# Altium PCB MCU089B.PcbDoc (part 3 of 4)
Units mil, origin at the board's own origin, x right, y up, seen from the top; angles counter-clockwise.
Board outline 2300 x 5500 mil, 4 copper layers (Top Signal, GND, PWR, Bottom Signal), stack 61.6 mil thick; 261 components, 208 nets, 964 pads, 377 vias.

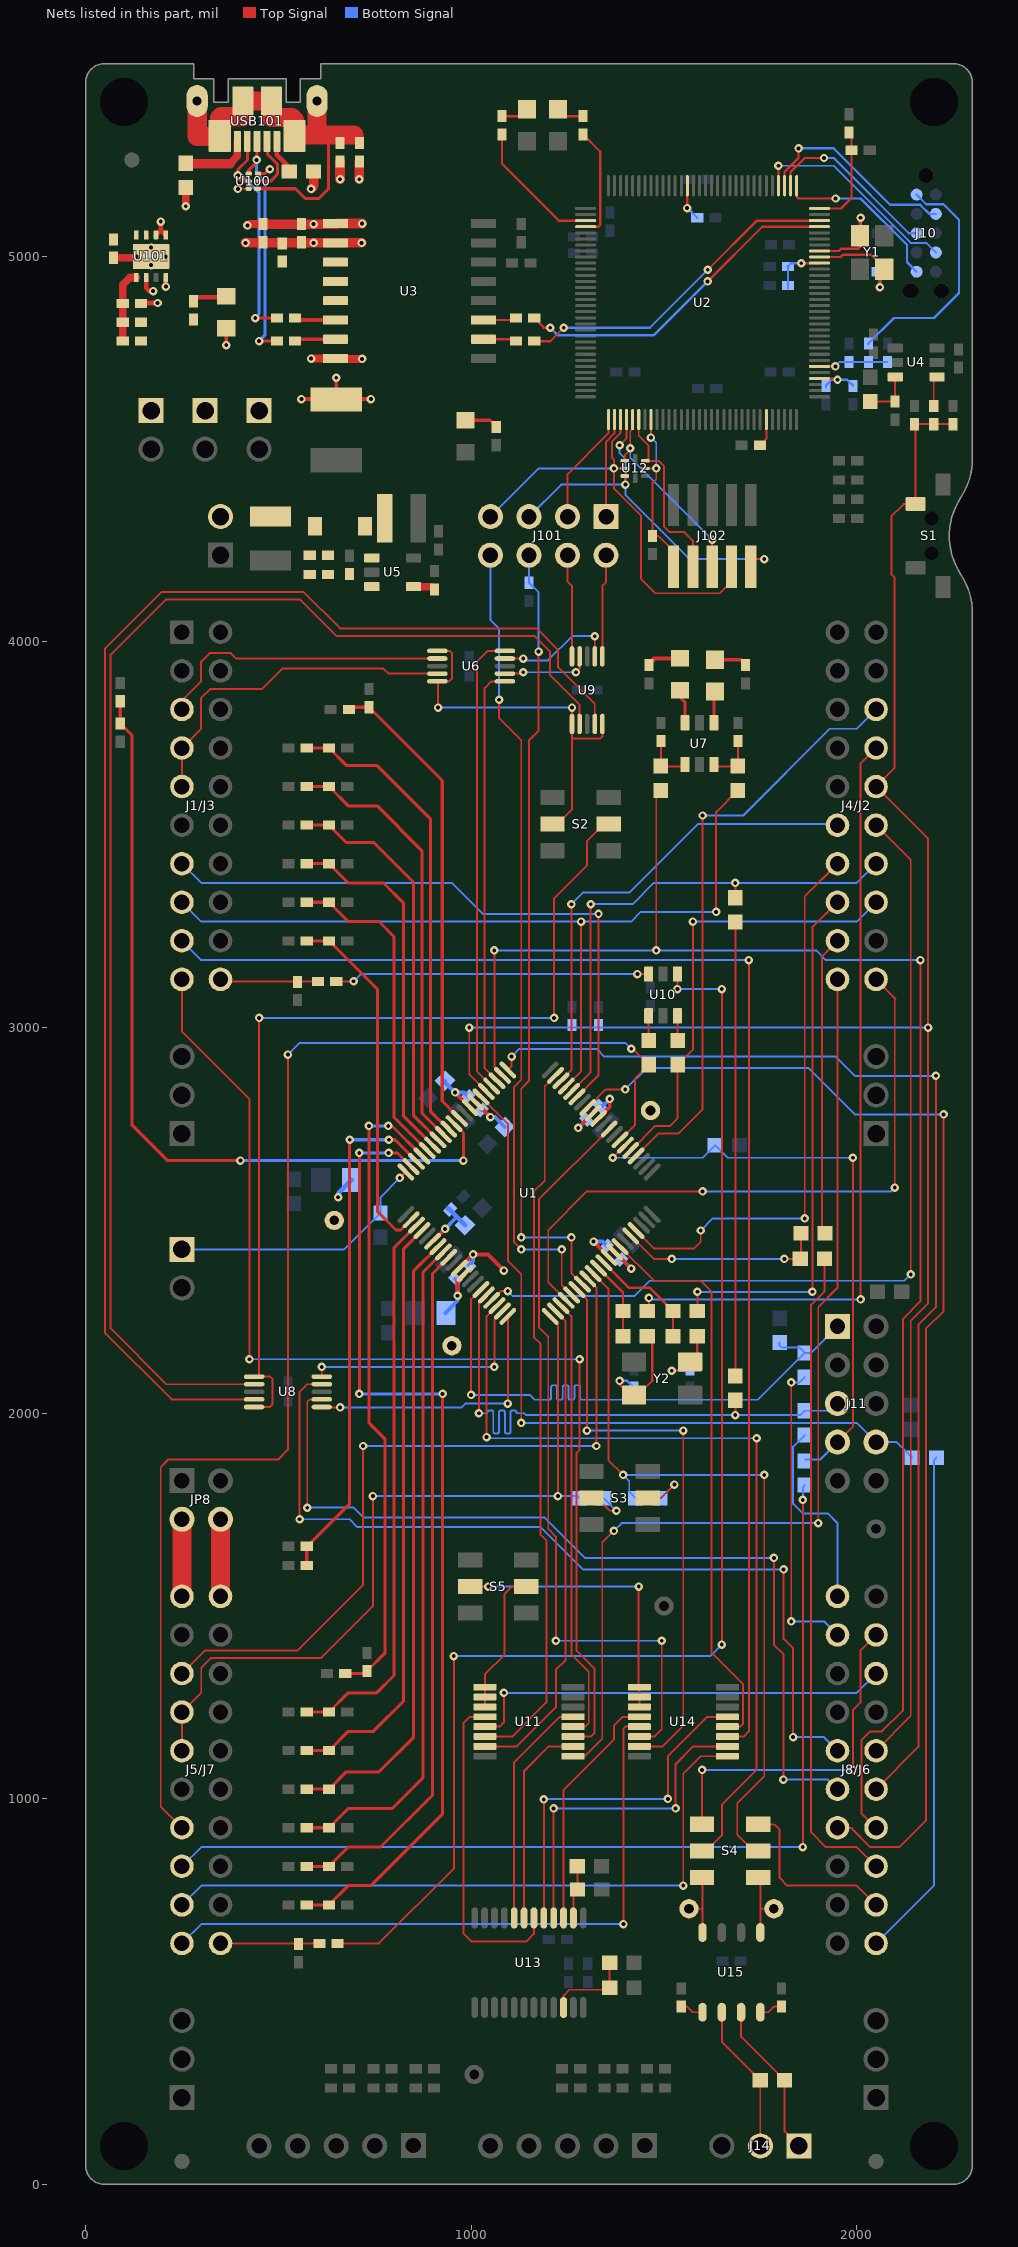
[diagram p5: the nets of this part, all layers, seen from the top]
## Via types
v1: diameter 22, hole 10, Top Signal to Bottom Signal, tented both sides, 377 vias

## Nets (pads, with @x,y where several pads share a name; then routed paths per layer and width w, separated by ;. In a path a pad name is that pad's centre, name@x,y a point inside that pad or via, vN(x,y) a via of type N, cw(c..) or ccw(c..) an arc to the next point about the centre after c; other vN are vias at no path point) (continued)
GPIO9: J1/J3.7 U1.75 | length 1631.7
  Top Signal w5: U1.75@1274.56,2820.4 1330.24,2876.08 v1(1330.24,3295)
  Bottom Signal w5: J1/J3.7@250,3425 300,3375 950,3375 1030,3295 v1(1330.24,3295)
GPIO10: J4/J2.14 R81.2 U1.76 | length 1328.1
  Top Signal w5: U1.76@1260.64,2834.32 1310,2883.68 v1(1310,3320) ; R81.2@1685,3336.5 v1(1685,3375)
  Bottom Signal w5: v1(1310,3320) 1418.62,3320 1473.62,3375 v1(1685,3375) 2000,3375 J4/J2.14@2050,3425
GPIO11: J4/J2.15 U1.37 | length 2327.6
  Top Signal w5: U1.37@1053.24,2292.86 1076.88,2316.5 v1(1095,2316.5) ; J4/J2.15@2050,3525 2140,3435 v1(2140,2360)
  Bottom Signal w5: v1(1095,2316.5) 1108.01,2303.48 1423.1,2303.48 1463.12,2343.5 2123.5,2343.5 v1(2140,2360)
GPIO12_BP: J8/J6.80 R50.2 | length 516.6
  Bottom Signal w5: R50.2@1865,1943.5 1835,1913.5 1835,1765.12 1860.12,1740 1925,1740 1950,1715 J8/J6.80@1950,1525
GPIO12_FSIRXD0: J11.5 R50.1 R51.1 U1.36 | length 1533.1
  Top Signal w5: v1(1020,2000) 1020,2287.45 U1.36@1039.32,2306.78 ; R51.1@1680,2033.5 1685,2028.5 v1(1685,1995)
  Bottom Signal w5: v1(1020,2000) 1034.84,2000 1039.34,2000 ccw(c1039.34,2003) 1042.34,2003 cw(c1046.84,2003) 1046.84,2007.5 1052.84,2007.5 cw(c1052.84,2003) 1057.34,2003 1057.34,2000 1057.34,1952 ccw(c1061.84,1952) 1061.84,1947.5 1067.84,1947.5 ccw(c1067.84,1952) 1072.34,1952 1072.34,2000 1072.34,2003 cw(c1076.84,2003) 1076.84,2007.5 1082.84,2007.5 cw(c1082.84,2003) 1087.34,2003 1087.34,2000 1087.34,1952 ccw(c1091.84,1952) 1091.84,1947.5 1097.84,1947.5 ccw(c1097.84,1952) 1102.34,1952 1102.34,2000 1102.34,2003 cw(c1106.84,2003) 1106.84,2007.5 1112.84,2007.5 cw(c1112.84,2003) 1117.34,2003 1117.34,2002.66 ccw(c1120,2002.66) 1120,2000 1138.01,2000 1143.01,1995 v1(1685,1995) 1853.5,1995 R50.1@1865,2006.5 1931.5,2006.5 J11.5@1950,2025
GPIO13_BP: J8/J6.79 R44.2 | length 795.1
  Top Signal w5: v1(1830,1460) v1(1830,2080)
  Bottom Signal w5: v1(1830,1460) 1915,1460 1945,1430 J8/J6.79@1950,1425 ; v1(1830,2080) 1851.5,2080 R44.2@1865,2093.5
GPIO13_FSIRXCLK: J11.1 R44.1 R46.1 U1.35 | length 1600.6
  Top Signal w5: v1(1000,2047.52) 1000,2295.29 U1.35@1025.4,2320.7
  Bottom Signal w5: v1(1000,2047.52) 1152.48,2047.52 1165,2035 1200,2035 1203,2035 ccw(c1203,2039.5) 1207.5,2039.5 1207.5,2068 cw(c1212,2068) 1212,2072.5 1218,2072.5 cw(c1218,2068) 1222.5,2068 1222.5,2039.5 ccw(c1227,2039.5) 1227,2035 1233,2035 ccw(c1233,2039.5) 1237.5,2039.5 1237.5,2068 cw(c1242,2068) 1242,2072.5 1248,2072.5 cw(c1248,2068) 1252.5,2068 1252.5,2039.5 ccw(c1257,2039.5) 1257,2035 1263,2035 ccw(c1263,2039.5) 1267.5,2039.5 1267.5,2068 cw(c1272,2068) 1272,2072.5 1278,2072.5 cw(c1278,2068) 1282.5,2068 1282.5,2039.5 ccw(c1287,2039.5) 1287,2035 1290.75,2035 1743.5,2035 R44.1@1865,2156.5 ; R46.1@1800,2183.5 1800,2175 1805,2170 1851.5,2170 R44.1@1865,2156.5 ; J11.1@1950,2225 1881.5,2156.5 R44.1@1865,2156.5
GPIO14: U1.79 U11.14 | length 1858.4
  Top Signal w5: U11.14@1035.83,1161.61 1106.61,1161.61 1195,1250 1195,1670 1180,1685 1180,2180 1162.8,2197.2 1162.8,2575 1190.84,2603.04 1190.84,2848.04 U1.79@1218.88,2876.08
GPIO14_BP: J8/J6.58 U11.13 | length 1116.3
  Top Signal w5: U11.13@1035.83,1187.2 1074.09,1187.2 1085.02,1198.13 v1(1085,1275)
  Bottom Signal w5: v1(1085,1275) 2000,1275 J8/J6.58@2050,1325
GPIO14_Q2A: U11.12 U13.6 | length 848.6
  Top Signal w5: U11.12@1035.83,1212.8 996.44,1212.8 980,1196.36 980,651.48 1001.48,630 1142.8,630 1162.8,650 U13.6@1162.8,691.14
GPIO15: J4/J2.35 U1.78 | length 1246.2
  Top Signal w5: U1.78@1232.8,2862.16 1260,2889.36 v1(1260,3320)
  Bottom Signal w5: v1(1260,3320) 1290,3350 1410,3350 1587.57,3527.57 1947.43,3527.57 J4/J2.35@1950,3525
GPIO16: U1.39 U8.10 | length 626.3
  Top Signal w5: U8.10@612.6,2094.87 v1(612.6,2120) ; v1(1060,2120) 1060,2243.94 U1.39@1081.08,2265.02
  Bottom Signal w5: v1(612.6,2120) v1(1060,2120)
GPIO16_BP: J8/J6.76 U8.9 | length 2280
  Top Signal w5: v1(555,1725) 555,2055.5 574.69,2075.19 U8.9@612.6,2075.19 ; v1(1810,1595) 1810,1415 1835,1390 v1(1835,1160)
  Bottom Signal w5: v1(555,1725) 684.59,1725 705,1704.59 1180.41,1704.59 1290,1595 v1(1810,1595) ; v1(1835,1160) 1915,1160 J8/J6.76@1950,1125
GPIO16_SCITX: U8.2 U9.2 | length 3653.9
  Top Signal w5: U8.2@437.4,2075.19 209.81,2075.19 65,2220 65,3967.34 207.66,4110 556.38,4110 651.38,4015 1165,4015 1205,3975 1205,3913.98 1281.21,3837.76 U9.2@1281.21,3787.4
GPIO17: U1.40 U8.6 | length 713.1
  Top Signal w5: U8.6@612.6,2016.13 613.73,2015 v1(660,2015) ; v1(1095,2025) U1.40@1095,2251.1
  Bottom Signal w5: v1(660,2015) 975,2015 985,2025 v1(1095,2025)
GPIO17_BP: J8/J6.75 U8.7 | length 2314.7
  Top Signal w5: v1(575,1755) 575,2029.88 580.93,2035.82 U8.7@612.6,2035.82 ; v1(1785,1625) 1785,1400 1810,1375 1809.84,1374.84 v1(1809.84,1050)
  Bottom Signal w5: v1(575,1755) 695,1755 720,1730 1190,1730 1295,1625 v1(1785,1625) ; v1(1809.84,1050) 1925,1050 J8/J6.75@1950,1025
GPIO17_SCIRX: U8.4 U9.4 | length 3762.7
  Top Signal w5: U8.4@437.4,2035.82 223.04,2035.82 50,2208.86 50,3981.78 198.22,4130 565,4130 660,4035 1170,4035 1225,3980 1225,3935.94 1320.58,3840.36 U9.4@1320.58,3787.4
GPIO18_BP: J4/J2.17 R36.1 | length 2033.2
  Top Signal w5: R36.1@1456.85,2265 1461.09,2269.24 v1(1461.09,2299.24) ; v1(2010,2295) 2010,3685 J4/J2.17@2050,3725
  Bottom Signal w5: v1(1461.09,2299.24) 1461.31,2299.24 1465.55,2295 v1(2010,2295)
GPIO18_X2: R32.1 R36.2 U1.50 | length 202.7
  Top Signal w6: U1.50@1330.24,2376.37 1393.86,2312.75 R36.2@1393.86,2265 R32.1@1393.86,2200
GPIO19_BP: J4/J2.33 R37.1 | length 1385.4
  Top Signal w5: R37.1@1586.5,2265 v1(1586.5,2314.88) ; v1(1884.88,2314.88) 1885,2315 1885,3260 J4/J2.33@1950,3325
  Bottom Signal w5: v1(1586.5,2314.88) v1(1884.88,2314.88)
GPIO19_X1: R33.1 R37.2 U1.51 | length 296.2
  Top Signal w6: U1.51@1344.16,2390.29 1409.45,2325 1463.5,2325 R37.2@1523.5,2265 R33.1@1523.5,2200
GPIO22: J5/J7.47 R42.1 U1.67 | length 3528
  Top Signal w5: J5/J7.47@250,925 195,980 195,1860 215,1880 500,1880 525,1905 v1(525,2930) ; U1.67@1385.92,2709.05 1425,2748.13 1425,2868.31 R42.1@1460.2,2903.5 1418.7,2945 v1(1415,2945)
  Bottom Signal w5: v1(525,2930) 555.36,2960.36 1399.64,2960.36 v1(1415,2945)
GPIO22_PWM_DAC: C48.1 J1/J3.30 R40.2 | length 254.8
  Top Signal w5: J1/J3.30@350,3125 355,3120 R40.2@602.76,3120
GPIO23: J4/J2.13 R43.1 U1.65 | length 1178.8
  Top Signal w5: U1.65@1413.75,2681.21 1477.55,2745 1515.9,2745 1535.63,2764.73 R43.1@1535.63,2903.5 1575,2942.87 v1(1575,3275)
  Bottom Signal w5: v1(1575,3275) 2000,3275 J4/J2.13@2050,3325
GPIO23_PWM_DAC: C47.1 J5/J7.70 R41.2 | length 256.4
  Top Signal w5: J5/J7.70@350,625 R41.2@606.38,625
GPIO24: J5/J7.44 J5/J7.45 R38.1 U1.41 | length 2044.2
  Top Signal w5: J5/J7.45@250,1125 J5/J7.44@250,1225 300,1275 300,1340 325,1365 610,1365 745,1500 745,1755 745.1,1755.1 v1(745.1,1785) ; U1.41@1204.96,2251.1 1225,2231.06 v1(1225,1785)
  Bottom Signal w5: v1(745.1,1785) v1(1225,1785) 1275.79,1785 R38.1@1280.79,1780
GPIO25: U1.42 U11.15 | length 1275.1
  Top Signal w5: U11.15@1035.83,1136.02 1118.82,1136.02 1220,1237.2 1220,1335 1245,1360 1245,2238.9 U1.42@1218.88,2265.02
GPIO25_BP: J4/J2.31 U11.1 | length 2615.5
  Top Signal w5: U11.1@1264.17,1110.43 1294.99,1110.43 1340,1155.44 1340,1665 v1(1370,1695) ; v1(1900,1715) 1900,2275 1950,2325 J4/J2.31@1950,3125
  Bottom Signal w5: v1(1370,1695) 1390,1715 v1(1900,1715)
GPIO25_Q2B: U11.2 U13.7 | length 534.5
  Top Signal w5: U13.7@1137.2,691.14 1137.2,1072.2 1201.02,1136.02 U11.2@1264.17,1136.02
GPIO26: U1.43 U11.4 | length 1157.1
  Top Signal w5: U1.43@1232.8,2278.94 1260,2251.74 1260,1375 1305,1330 1305,1196.36 1295.85,1187.2 U11.4@1264.17,1187.2
GPIO26_BP: J1/J3.10 U11.3 | length 2964.7
  Top Signal w5: J1/J3.10@250,3125 250,2990 425,2815 v1(425,2140) ; U11.3@1264.17,1161.61 1310,1161.61 1320,1171.61 1320,1336.8 1273.29,1383.51 1273.29,1897.07 1281.21,1905 v1(1281.21,2140)
  Bottom Signal w5: v1(425,2140) v1(1281.21,2140)
GPIO26_Q2I: U11.5 U13.8 | length 605
  Top Signal w5: U13.8@1111.61,691.14 1111.61,1094.72 1229.69,1212.8 U11.5@1264.17,1212.8
GPIO27: J4/J2.11 U1.44 | length 1706.8
  Top Signal w5: U1.44@1246.72,2292.86 1200,2339.58 1200,2474.79 1300.21,2575 v1(1600,2575) ; J4/J2.11@2050,3125 2100,3075 2098.5,3073.5 v1(2098.5,2585)
  Bottom Signal w5: v1(1600,2575) 2088.5,2575 v1(2098.5,2585)
GPIO28: U1.4 U6.10 | length 1200.8
  Top Signal w5: U1.4@1053.24,2848.24 1015,2886.48 1015,3949.2 1042.56,3976.76 U6.10@1087.57,3976.76
GPIO28_BP: J1/J3.3 U6.2 | length 772.2
  Top Signal w5: J1/J3.3@250,3825 250,3847.93 299.81,3897.74 299.81,3949.2 321.61,3971 376.73,3971 390.65,3957.08 U6.2@912.38,3957.08
GPIO28_SCIRX: U6.9 U9.7 | length 313.7
  Top Signal w5: U6.9@1087.57,3957.08 v1(1135,3957.08) ; U9.7@1320.58,3962.6 1320,3963.18 1320.58,3963.77 v1(1320.58,4015)
  Bottom Signal w5: v1(1135,3957.08) 1139.61,3952.47 1199.22,3952.47 1261.76,4015 v1(1320.58,4015)
GPIO29: U1.3 U6.6 | length 1091.4
  Top Signal w5: U1.3@1067.16,2862.16 1035,2894.32 1035,3880.3 1052.72,3898.02 U6.6@1087.57,3898.02
GPIO29_BP: J1/J3.4 J1/J3.5 U6.4 | length 900
  Top Signal w5: J1/J3.5@250,3625 J1/J3.4@250,3725 299.81,3774.81 299.81,3854.81 322.93,3877.93 457.5,3877.93 510.53,3930.96 772.51,3930.96 785.76,3917.71 U6.4@912.38,3917.71
GPIO29_SCITX: U6.7 U9.9 | length 230.8
  Top Signal w5: U6.7@1087.57,3917.71 1131.21,3917.71 v1(1135,3921.5) ; v1(1271.76,3921.5) 1281.21,3930.96 U9.9@1281.21,3962.6
  Bottom Signal w5: v1(1135,3921.5) v1(1271.76,3921.5)
GPIO30: J8/J6.55 U1.1 | length 3095.6
  Top Signal w5: U1.1@1095,2890 1105,2900 v1(1105,2925) v1@1105,2930 ; J8/J6.55@2050,1025 2160,1135 2160,2230 2205,2275 v1(2205,2875)
  Bottom Signal w5: v1(1105,2925) 1125,2945 1325.63,2945 1345.63,2925 1945,2925 1995,2875 v1(2205,2875)
GPIO31: J8/J6.54 R34.1 U1.2 | length 4214.7
  Top Signal w5: v1(1060,3200) 1060,2897.16 U1.2@1081.08,2876.08 ; v1(1480,3200) 1480,3602.99 R34.1@1492.04,3615.03 ; J8/J6.54@2050,925 2011.99,963.01 2011.99,1151.99 2035,1175 2065,1175 2120,1230 2120,2245 2165,2290 v1(2165,3175)
  Bottom Signal w5: v1(1060,3200) v1(1480,3200) 1895,3200 1920,3175 v1(2165,3175)
GPIO32: R39.2 S4.2 U1.49 | length 2028.1
  Top Signal w5: U1.49@1316.32,2362.45 1355.91,2322.87 1355.91,1877.95 v1(1393.86,1840) ; S4.2@1744.57,865 1732.2,865 1690,907.2 1690,988.39 1760,1058.39 v1(1760,1840)
  Bottom Signal w5: R39.2@1426.46,1780 1410,1796.46 1410,1823.86 v1(1393.86,1840) v1(1760,1840)
GPIO32_BP: J8/J6.52 S4.3 | length 465.2
  Top Signal w5: S4.3@1744.57,933.9 1786.1,933.9 1800,920 1800,795 1820,775 2000,775 J8/J6.52@2050,725
GPIO32_CANTX: S4.1 TP7.1 U15.1 | length 195
  Top Signal w5: S4.1@1744.57,796.1 1750,790.67 1750,715 ; U15.1@1750,653.35 1750,715 ; TP7.1@1800,715 1750,715
GPIO33: S4.5 U1.38 | length 2188.3
  Top Signal w5: v1(1040,1938.09) 1040,2251.78 U1.38@1067.16,2278.94 ; S4.5@1598.9,865 1610,865 1650,905 1650,985 1740,1075 v1(1740,1935)
  Bottom Signal w5: v1(1040,1938.09) 1043.09,1935 v1(1740,1935)
GPIO33_BP: J8/J6.59 S4.6 | length 907.1
  Top Signal w5: S4.6@1598.9,933.9 v1(1598.9,1075) ; v1(1990,1075) 1990,1230 2010,1250 2010,1385 J8/J6.59@2050,1425
  Bottom Signal w5: v1(1598.9,1075) v1(1990,1075)
GPIO33_CANRX: S4.4 TP8.1 U15.4 | length 193.4
  Top Signal w5: TP8.1@1549.86,715 1600,715 ; S4.4@1598.9,796.1 1600,795 1600,715 ; U15.4@1600,653.35 1600,715
GPIO34: J1/J3.8 R35.1 U1.77 | length 2196.9
  Top Signal w5: U1.77@1246.72,2848.24 1285,2886.52 v1(1285,3275) ; v1(1635,3300) 1635,3558.99 R35.1@1691.04,3615.03
  Bottom Signal w5: J1/J3.8@250,3325 300,3275 v1(1285,3275) 1415,3275 1440,3300 v1(1635,3300)
GPIO35: J5/J7.43 U1.48 | length 1973.2
  Top Signal w5: J5/J7.43@250,1325 310,1385 550,1385 720,1555 720,1885 v1(720,1915) ; U1.48@1302.4,2348.53 1325,2325.93 v1(1325,1915)
  Bottom Signal w5: v1(720,1915) v1(1325,1915)
GPIO37: U1.46 U14.15 | length 1527.7
  Top Signal w5: U1.46@1274.56,2320.7 1300,2295.26 v1(1300,1955) ; U14.15@1436.21,1136.02 1496.54,1136.02 1550,1189.49 v1(1550,1955)
  Bottom Signal w5: v1(1300,1955) v1(1550,1955)
GPIO37_BP: J5/J7.49 U14.1 | length 1744.4
  Top Signal w5: v1(1550,775) 1550,1065 1549.86,1065.14 1595.16,1110.43 U14.1@1664.56,1110.43
  Bottom Signal w5: J5/J7.49@250,725 300,775 v1(1550,775)
GPIO37_Q1B: U13.4 U14.2 | length 868.7
  Top Signal w5: U13.4@1213.98,691.14 v1(1213.98,975) ; v1(1530,975) 1530,1090.36 1575.66,1136.02 U14.2@1664.56,1136.02
  Bottom Signal w5: v1(1213.98,975) v1(1530,975)
GPIO39: R69.1 R71.2 U1.56 | length 531.7
  Top Signal w5: U1.56@1413.75,2459.89 1473.64,2400 v1(1520,2400) ; v1(1812.13,2400) 1853.03,2400 R71.2@1853.5,2400.47 1855,2401.97 R69.1@1855,2466.8
  Bottom Signal w5: v1(1520,2400) v1(1812.13,2400)
GPIO40: J4/J2.18 U1.64 | length 1548.1
  Top Signal w5: U1.64@1427.67,2667.29 1485.38,2725 1536.7,2725 1600,2788.3 v1(1600,3550)
  Bottom Signal w5: v1(1600,3550) 1705,3550 1930,3775 2000,3775 J4/J2.18@2050,3825
GPIO41_BP: J5/J7.48 R55.2 | length 2571.3
  Top Signal w5: v1(1860,875) v1(1860,1775)
  Bottom Signal w5: J5/J7.48@250,825 300,875 v1(1860,875) ; v1(1860,1775) 1860,1808.5 R55.2@1865,1813.5
GPIO41_FSIRXD1: J11.7 R55.1 R56.1 U1.66 | length 1552.3
  Top Signal w5: v1(1367.12,2662.41) U1.66@1399.84,2695.13 ; J11.7@1950,1925 1990,1965 v1(1990,2662.41)
  Bottom Signal w5: v1(1367.12,2662.41) 1600.47,2662.41 R56.1@1633.06,2695 1665.65,2662.41 v1(1990,2662.41) ; R55.1@1866.5,1880 1905,1880 J11.7@1950,1925
GPIO42: J4/J2.34 U1.57 | length 1461.1
  Top Signal w5: U1.57@1427.67,2473.81 1474.48,2427 1577.43,2427 1595.43,2445 v1(1595.43,2473.81) ; v1(1865,2505) 1865,3340 J4/J2.34@1950,3425
  Bottom Signal w5: v1(1595.43,2473.81) 1626.62,2505 v1(1865,2505)
GPIO43: U1.54 U14.4 | length 1483.8
  Top Signal w5: U1.54@1385.92,2432.05 1474.46,2343.5 1595.43,2343.5 1623.62,2315.32 1623.62,1378.62 1705,1297.24 1705,1195 1697.2,1187.2 U14.4@1664.56,1187.2
GPIO43_BP: J1/J3.9 U14.3 | length 3551.7
  Top Signal w5: U14.3@1664.56,1161.61 1706.61,1161.61 1720,1175 v1(1720,3175)
  Bottom Signal w5: J1/J3.9@250,3225 300,3175 v1(1720,3175)
GPIO43_Q1I: U13.5 U14.5 | length 936.9
  Top Signal w5: U13.5@1188.39,691.14 v1(1188.39,998.39) ; v1(1510,1000) 1510,1110.47 1612.32,1212.8 U14.5@1664.56,1212.8
  Bottom Signal w5: v1(1188.39,998.39) 1190,1000 v1(1510,1000)
GPIO44: U1.69 U14.14 | length 1990.3
  Top Signal w5: v1(1220,1410) 1220,1680 1200,1700 1200,2198.5 1175.55,2222.95 1175.55,2554.36 U1.69@1358.08,2736.89 ; U14.14@1436.21,1161.61 1475,1161.61 1494.25,1180.86 v1(1494.25,1410)
  Bottom Signal w5: v1(1220,1410) v1(1494.25,1410)
GPIO44_BP: J5/J7.50 U14.13 | length 1716.1
  Top Signal w5: v1(1395,675) 1395,1182.13 1400.08,1187.2 U14.13@1436.21,1187.2
  Bottom Signal w5: J5/J7.50@250,625 300,675 v1(1395,675)
GPIO44_Q1A: U13.3 U14.12 | length 628.2
  Top Signal w5: U13.3@1239.57,691.14 1239.57,1023.25 1369.88,1153.56 1369.88,1189.37 1393.31,1212.8 U14.12@1436.21,1212.8
GPIO45: J8/J6.74 U1.73 | length 3143.1
  Top Signal w5: U1.73@1302.4,2792.56 1349.45,2839.62 v1(1399.62,2839.62) ; J8/J6.74@1950,925 1985,925 2035,875 2110,875 2180,945 2180,2220.02 2225,2265.02 v1(2225,2775)
  Bottom Signal w5: v1(1399.62,2839.62) 1455,2895 1875,2895 1995,2775 v1(2225,2775)
GPIO46_BP: J8/J6.51 R54.2 | length 1324.8
  Bottom Signal w5: J8/J6.51@2050,625 2200,775 2200,1878.5 R54.2@2206.5,1885
GPIO46_FSITXD1: J11.8 R54.1 U1.6 | length 1939.5
  Top Signal w5: U1.6@1025.4,2820.4 1095,2750.81 1095,2395 1130,2360 v1(1130,1975)
  Bottom Signal w5: v1(1130,1975) 2000,1975 J11.8@2050,1925 2103.5,1925 R54.1@2143.5,1885
ITCK: J10.4 U2.100 | length 553.2
  Top Signal w5: U2.100@1796.85,5183.15 v1(1796.85,5235)
  Bottom Signal w5: v1(1796.85,5235) 1939.85,5235 2139.85,5035 2180,5035 J10.4@2205,5010
ITDI: J10.8 U2.98 | length 457.8
  Top Signal w6: U2.98@1828.35,5183.15 1828.35,5218.35 1865,5255 v1(1915,5255)
  Bottom Signal w6: v1(1915,5255) 1940,5255 2135,5060 J10.8@2155,5060
ITDO: J10.6 U2.97 | length 446.2
  Top Signal w6: U2.97@1844.09,5183.15 1844.09,5154.91 1849,5150 v1(1945,5150)
  Bottom Signal w6: v1(1945,5150) 2010,5150 2130,5030 2130,4985 J10.6@2155,4960
ITMS: J10.2 U2.99 | length 538.3
  Top Signal w6: U2.99@1812.6,5183.15 1812.6,5218.35 1849.09,5254.84 v1(1849.09,5280)
  Bottom Signal w6: v1(1849.09,5280) 1940,5280 2086,5134 2164.23,5134 2188.23,5110 J10.2@2205,5110
MCU_RXD: J101.2 U9.6 | length 266.4
  Top Signal w5: U9.6@1340.27,3962.6 1340.27,4145.27 1350,4155 J101.2@1350,4225
MCU_TCK: J101.8 U1.45 | length 2082.3
  Top Signal w5: v1(1072.27,3850) 1072.27,3802.73 1130,3745 1130,2865 1111.5,2846.5 1111.5,2443.5 v1(1130,2425) ; v1(1235,2425) 1235,2332.42 U1.45@1260.64,2306.78
  Bottom Signal w5: J101.8@1050,4225 1050,4057 1072.27,4034.73 v1(1072.27,3850) ; v1(1130,2425) v1(1235,2425)
MCU_TMS: J101.6 R10.1 U1.47 | length 2061.2
  Top Signal w5: v1(1130,2455.71) 1130,2841.99 1150,2861.99 1150,3745 1175,3770 v1(1175,3975) ; v1(1260,2455.71) 1260,2363.09 U1.47@1288.48,2334.61
  Bottom Signal w5: v1(1130,2455.71) v1(1260,2455.71) ; J101.6@1150,4225 R10.1@1150,4153.62 1175,4128.62 v1(1175,3975)
MCU_TXD: J101.4 U9.10 | length 267.2
  Top Signal w5: J101.4@1250,4225 1250,4156.53 1261.53,4145 U9.10@1261.53,3962.6
NetC3_1: C3.1 C4.1 D1.1 JP9.2 R7.2
NetC3_2: C3.2 R7.1 R9.2 U5.3
NetC8_1: C8.1 R6.1 U4.6 | length 130.8
  Top Signal w5: R6.1@2034.61,4623.62 C8.1@2099.02,4623.62 U4.6@2099.02,4690
NetC24_1: C24.1 J15.1 U1.20 | length 687.5
  Top Signal w5: v1(815,2610) U1.20@830.53,2625.53
  Bottom Signal w5: J15.1@250,2425 670.78,2425 C24.1@765,2519.22 765,2560 v1(815,2610)
NetC25_1: C25.1 R12.2 U1.19 | length 2529.3
  Top Signal w8: R12.2@573.62,725 C25.1@631.38,725 681.38,775 740,775 925.96,960.96 v1(925.96,2050) ; v1(710,2050) 710,2110 v1(710,2675) ; v1(785.95,2675) 808.9,2675 U1.19@844.45,2639.45
  Bottom Signal w8: v1(710,2050) v1(925.96,2050) ; v1(710,2675) v1(785.95,2675)
NetC26_1: C26.1 R14.2 U1.13 | length 1126.4
  Top Signal w8: R14.2@573.62,3625 C26.1@631.38,3625 681.38,3575 756.16,3575 872.29,3458.87 872.29,2778.64 U1.13@927.97,2722.97
NetC27_1: C27.1 R16.2 U1.27 | length 1631.6
  Top Signal w8: R16.2@573.62,1025 C27.1@631.38,1025 676.38,1070 761.16,1070 850,1158.84 850,2368 U1.27@914.05,2432.05
NetC28_1: C28.1 R18.2 U1.10 | length 1217.6
  Top Signal w8: R18.2@682.93,3825 688.61,3830.68 C28.1@735,3830.68 925,3640.68 925,2809.45 U1.10@969.73,2764.73
NetC29_1: C29.1 R20.2 U1.24 | length 1544.4
  Top Signal w8: R20.2@573.62,1125 C29.1@631.38,1125 681.38,1175 746.38,1175 825,1253.62 825,2426.52 U1.24@872.29,2473.81
NetC30_1: C30.1 R22.2 U1.29 | length 1814.6
  Top Signal w8: R22.2@573.62,825 C30.1@631.38,825 681.38,875 765,875 900,1010 900,2362.33 U1.29@941.89,2404.21
NetC31_1: C31.1 R24.2 U1.22 | length 930.2
  Top Signal w8: R24.2@573.62,3225 C31.1@631.38,3225 757.59,3098.79 757.59,2522.41 805,2475 817.8,2475 U1.22@844.45,2501.65
NetC32_1: C32.1 R26.2 U1.14 | length 1032.4
  Top Signal w8: R26.2@573.62,3525 C32.1@631.38,3525 676.38,3480 747.33,3480 850,3377.33 850,2773.1 U1.14@914.05,2709.05
NetC33_1: C33.1 R13.2 U1.18 | length 1346.6
  Top Signal w8: R13.2@573.62,1605 573.62,1653.62 685,1765 v1(685,2709.05) ; v1(786.9,2709.05) 802.69,2709.05 U1.18@858.37,2653.37
  Bottom Signal w8: v1(685,2709.05) v1(786.9,2709.05)
NetC34_1: C34.1 R15.2 U1.12 | length 1221.5
  Top Signal w8: R15.2@573.62,3725 C34.1@631.38,3725 676.38,3680 755,3680 895,3540 895,2782.17 940.29,2736.89 U1.12@941.89,2736.89
NetC35_1: C35.1 R17.2 U1.17 | length 1678.3
  Top Signal w8: R17.2@673.62,1325 723.62,1325 C35.1@730,1331.38 776.16,1377.54 776.16,1933.84 740,1970 735,1975 v1(735,2745) ; v1(785,2745) 794.58,2745 U1.17@872.29,2667.29
  Bottom Signal w8: v1(735,2745) v1(785,2745)
NetC36_1: C36.1 R19.2 U1.23 | length 1457.6
  Top Signal w8: R19.2@573.62,1225 C36.1@631.38,1225 681.38,1275 755,1275 800,1320 800,2429.36 U1.23@858.37,2487.73
NetC37_1: C37.1 R21.2 U1.28 | length 1740.3
  Top Signal w8: R21.2@573.62,925 C37.1@631.38,925 681.38,975 795,975 875,1055 875,2365.16 U1.28@927.97,2418.13
NetC38_1: C38.1 R23.2 U1.16 | length 853.6
  Top Signal w8: R23.2@573.62,3325 C38.1@631.38,3325 681.38,3275 760.83,3275 800,3235.83 800,2767.42 U1.16@886.21,2681.21
NetC39_1: C39.1 R25.2 U1.15 | length 952.5
  Top Signal w8: R25.2@573.62,3425 C39.1@631.38,3425 681.38,3375 772.82,3375 825,3322.82 825,2770.26 U1.15@900.13,2695.13
NetC40_1: C40.1 R27.2 U1.11 | length 2115.3
  Top Signal w8: R27.2@90,3846.38 C40.1@90,3788.62 120,3758.62 120,2747.8 212.8,2655 v1(401.63,2655) ; U1.11@955.81,2750.81 980,2726.61 v1(980,2655)
  Bottom Signal w8: v1(401.63,2655) v1(980,2655)
NetC50_1: C50.1 R62.2 U2.96 | length 267.2
  Top Signal w6: U2.96@1903.15,5124.09 1959.09,5124.09 1986.38,5151.38 C50.1@1986.38,5275 1986.38,5315 R62.2@1980,5321.38
NetC59_1: C59.1 C60.1 C61.1 U2.87 U2.115 | length 237.7
  Top Signal w6: v1(1560,5125) 1560.63,5125.63 U2.115@1560.63,5183.15 ; v1(1856,4982) 1862,4982 1862.36,4982.36 U2.87@1903.15,4982.36
  Bottom Signal w6: v1(1560,5125) 1561.38,5125 C61.1@1586.38,5100 ; C59.1@1821,4974 1829,4982 1846,4982 v1(1856,4982) ; C60.1@1821.62,4917.62 C60.1@1821.62,4924 1821.62,4972.62 C59.1@1823,4974
NetC62_1: C62.1 U2.89 Y1.3 | length 227.7
  Top Signal w6: U2.89@1903.15,5013.86 1953.86,5013.86 1960,5020 2004,5020 2009,5025 2008,5026 Y1.3@2008,5053
  Top Signal w8: Y1.3@2008.5,5053.31 2008.5,5098.5 v1(2010,5100)
  Bottom Signal w8: C62.1@2006.38,5060 2010,5063.62 v1(2010,5100)
NetC63_1: C63.1 U2.88 Y1.1 | length 283.5
  Top Signal w6: U2.88@1903.15,4998.11 1957.89,4998.11 1964,5004.22 2036.78,5004.22 2073,4968 Y1.1@2073,4966
  Top Signal w8: v1(2060,4920) 2060,4955.2 Y1.1@2071.5,4966.69
  Bottom Signal w8: C63.1@2053.62,4960 2053.62,4949.37 2060,4942.99 v1(2060,4920)
NetC66_1: C66.1 R70.1 U2.68 | length 137
  Top Signal w6: U2.68@1903.15,4683.15 1946.85,4683.15 v1(1950,4680)
  Bottom Signal w6: R70.1@1920,4660 1920,4665 1935,4680 v1(1950,4680) 1975,4680 1990,4665 C66.1@1990,4663.62
NetC101_1: C101.1 R100.2 U100.1 USB101.6 USB101.7 USB101.8 USB101.9 USB101.10 USB101.11 | length 1103.4
  Top Signal w8: U100.1@445.83,5175.31 544.69,5175.31 570,5150 605,5150 630,5175 630,5314.8 630,5315
  Top Signal w50: USB101.10@289.49,5402.91 289.49,5310.51 USB101.11@346.2,5310.51 ; USB101.11@348.05,5312.36 348.05,5358.05 350,5360 ; 351.91,5361.91 408.09,5361.91 USB101.9@408.09,5402.91 USB101.8@481.91,5402.91 481.91,5361.91 ; 480,5360 535,5360 541.95,5353.05 USB101.6@541.95,5314.8 ; USB101.6@539.51,5314.8 USB101.6@541.95,5314.8 ; USB101.6@541.95,5312.36 USB101.6@541.95,5314.8 ; USB101.7@600,5402.4 600,5314.8 ; 695.2,5314.8 630,5314.8 600,5314.8 ; USB101.6@541.95,5314.8 600,5314.8
NetC102_2: C102.2 R101.1 R102.2 U101.5 | length 189.4
  Top Signal w20: C102.2@96,4828 96.38,4827.62 R101.1@96.38,4780 ; C102.2@96.38,4828 C102.2@96.38,4829 R102.2@96.38,4878 96.38,4926.38 114.88,4944.88 U101.5@131.61,4944.88
NetC106_2: C106.2 U3.3 U3.4 U3.5
NetD1_2: D1.2 L1.2 U5.1
NetJ4/J2_32: J4/J2.32 R69.2 | length 778.1
  Top Signal w5: R69.2@1917.99,2466.8 1910,2474.79 1910,3185 J4/J2.32@1950,3225
NetJ5/J7_41: J5/J7.41 JP8.3 | length 200
  Top Signal w50: J5/J7.41@250,1525 JP8.3@250,1725
NetJ5/J7_61: J5/J7.61 JP8.4 | length 200
  Top Signal w50: J5/J7.61@350,1525 JP8.4@350,1725
NetJ8/J6_53: J8/J6.53 R71.1 | length 1706.6
  Top Signal w5: R71.1@1916.5,2400.47 1916.5,2316.5 1881.5,2281.5 1881.5,913.5 1920,875 2000,875 J8/J6.53@2050,825
NetJ10_10: J10.10 R66.1 | length 616.3
  Bottom Signal w6: R66.1@2030,4773.62 2096.38,4840 2200,4840 2265,4905 2265,5095 2225,5135 2180,5135 J10.10@2155,5160
NetJ14_1: J14.1 R79.2 U15.7 | length 408.8
  Top Signal w5: U15.7@1700,446.65 1700,382.6 R79.2@1812.6,270 1812.6,137.4 J14.1@1850,100
NetJ14_2: J14.2 R79.1 U15.6 | length 388.1
  Top Signal w5: U15.6@1650,446.65 1650,369.61 R79.1@1749.61,270 1749.61,100.39 J14.2@1750,100
NetL100_1: L100.1 USB101.5 | length 91.6
  Top Signal w12: USB101.5@496.18,5298.19 496.18,5263.82 528.5,5231.5 L100.1@528.5,5220
NetL101_1: L101.1 USB101.1 | length 179.3
  Top Signal w20: 374.61,5240 393.82,5259.21 USB101.1@393.82,5298.19
  Top Signal w25: L101.1@261.5,5240 374.61,5240
NetLED0_2: LED0.2 R105.1 | length 169.7
  Top Signal w8: R105.1@280,4885 R105.1@286.5,4891.5 ; LED0.2@361.5,4891.5 R105.1@286.5,4891.5 ; LED0.2@365,4890 LED0.2@365,4895 ; LED0.2@365,4896.34 291.34,4896.34 R105.1@286.5,4891.5
NetLED1_2: LED1.2 R3.1 | length 86.8
  Top Signal w8: LED1.2@985,4575 1048.66,4575 R3.1@1065,4558.66
NetLED2_1: LED2.1 R63.1 | length 71.8
  Top Signal w6: R63.1@1080,5363.62 1128.62,5363.62 LED2.1@1145,5380
NetLED3_1: LED3.1 R64.1 | length 71.8
  Top Signal w6: LED3.1@1225,5380 1241.38,5363.62 R64.1@1290,5363.62
NetLED4_1: LED4.1 U7.6 | length 95.2
  Top Signal w5: U7.6@1552.04,3786.53 U7.6@1552.04,3790.66
  Top Signal w8: LED4.1@1542.04,3876.53 1542.04,3856.53 1554.64,3843.93 U7.6@1554.64,3790.66
NetLED4_2: LED4.2 R28.1 | length 171.5
  Top Signal w8: R28.1@1461.41,3939.99 1477.95,3956.53 LED4.2@1542.04,3956.53 ; R28.1@1462.04,3946.53 1473.22,3957.71 LED4.2@1541.41,3957.71
NetLED5_1: LED5.1 R29.1 | length 85.1
  Top Signal w8: LED5.1@1632.04,3953.87 1699.7,3953.87 R29.1@1712.04,3941.53
NetLED5_2: LED5.2 U7.4 | length 81.9
  Top Signal w8: U7.4@1629.44,3790.66 1629.44,3868.93 LED5.2@1632.04,3871.53
NetR1_1: R1.1 U3.11 | length 123.3
  Top Signal w6: U3.11@1027.01,4835 R1.1@1115,4835 ; R1.1@1115,4835 R1.1@1120,4840 ; R1.1@1115,4835 R1.1@1120,4840 ; R1.1@1115,4835 R1.1@1120,4840 ; R1.1@1115,4835 R1.1@1120,4840 ; R1.1@1115,4835 R1.1@1120,4840
NetR2_1: R2.1 U3.10 | length 123.3
  Top Signal w6: U3.10@1027.01,4785 R2.1@1115,4785 ; R2.1@1115,4785 R2.1@1120,4780 ; R2.1@1115,4785 R2.1@1120,4780 ; R2.1@1115,4785 R2.1@1120,4780 ; R2.1@1115,4785 R2.1@1120,4780 ; R2.1@1115,4785 R2.1@1120,4780
NetR5_1: R5.1 U4.1 | length 79.1
  Top Signal w5: R5.1@2199.61,4612 2199.61,4679.05 U4.1@2208.15,4687.6
NetR8_1: R8.1 U5.4 | length 57.3
  Top Signal w20: U5.4@850.6,4143.37 898.01,4143.37 R8.1@905,4136.38
NetR30_1: R30.1 R34.2 U7.1 | length 126.4
  Top Signal w5: R30.1@1492.04,3742.9 R34.2@1492.04,3678.02 1492.04,3676.53 U7.1@1552.04,3676.53
NetR31_1: R31.1 R35.2 U7.3 | length 136.4
  Top Signal w5: U7.3@1632.04,3676.53 R35.2@1702.04,3676.53 ; R35.2@1692.04,3676.53 1692.04,3678.02 R31.1@1692.04,3742.9
NetR38_2: R38.2 S3.5 | length 124.6
  Top Signal w5: S3.5@1312.28,1780 1325.86,1780 1358.77,1747.09 v1(1376.69,1747.09)
  Bottom Signal w5: R38.2@1343.78,1780 v1(1376.69,1747.09)
NetR39_1: R39.1 S3.2 | length 135.7
  Top Signal w5: S3.2@1457.95,1780 1492.04,1780 v1(1527.04,1815)
  Bottom Signal w5: R39.1@1489.45,1780 1492.04,1780 v1(1527.04,1815)
NetR40_1: R40.1 U10.6 | length 818
  Top Signal w5: R40.1@650,3120 v1(695,3120) ; v1(1431.24,3138.76) U10.6@1460.2,3138.76
  Bottom Signal w5: v1(695,3120) 713.76,3138.76 v1(1431.24,3138.76)
NetR41_1: R41.1 U10.4 | length 3493.8
  Top Signal w5: R41.1@653.62,625 760.75,625 955,819.25 v1(955,1370) ; v1(1535,3100) U10.4@1535,3138.76 ; v1(1650,1400) v1(1650,3100)
  Bottom Signal w5: v1(955,1370) 1620,1370 v1(1650,1400) ; v1(1535,3100) v1(1650,3100)
NetR42_2: R42.2 U10.1 | length 64
  Top Signal w5: R42.2@1460.2,2966.5 U10.1@1460.2,3030.49
NetR43_2: R43.2 U10.3 | length 64.3
  Top Signal w5: U10.3@1535,3030.49 1535.63,3029.86 R43.2@1535.63,2966.5
NetR47_1: R47.1 R52.2 U13.2 | length 138.5
  Top Signal w5: U13.2@1265.16,691.14 1265.16,754.25 R52.2@1275.9,765 1275.9,824.45 R47.1@1275.35,825
NetR48_1: R48.1 R53.1 U13.22 | length 223.9
  Top Signal w5: U13.22@1239.57,458.86 1239.57,489.57 1255,505 1354.25,505 R53.1@1359.25,510 R48.1@1359.25,575
NetR51_2: R51.2 R81.1 | length 1199.1
  Top Signal w5: R51.2@1680,2096.5 R51.2@1685,2096.5 1697.07,2096.5 1685,2108.57 R81.1@1685,3273.5
NetR63_2: R63.2 U2.3 | length 354.3
  Top Signal w6: R63.2@1080,5316.38 1080,5240 1227.4,5092.6 U2.3@1296.85,5092.6
NetR64_2: R64.2 U2.4 | length 293.5
  Top Signal w6: R64.2@1290,5316.38 1335,5271.38 1335,5081.61 1330.24,5076.85 U2.4@1296.85,5076.85
NetR65_1: R65.1 R66.2 R67.2 U2.70 | length 181.7
  Top Signal w5: U2.70@1903.15,4714.65 v1(1944.65,4714.65)
  Bottom Signal w5: v1(1944.65,4714.65) 1956.38,4726.38 R65.1@1980,4726.38 R66.2@2030,4726.38 R67.2@2080,4726.38
NetR68_2: R68.2 U2.59 | length 73.7
  Top Signal w5: R68.2@1748.62,4510.11 1765.35,4526.84 U2.59@1765.35,4576.85
NetR78_1: R78.1 U15.5 | length 61.2
  Top Signal w5: R78.1@1544.88,461.38 1560,461.38 1574.72,446.65 U15.5@1600,446.65
NetR80_2: R80.2 U15.8 | length 61.1
  Top Signal w5: U15.8@1750,446.65 1770.28,446.65 1785,461.38 R80.2@1805,461.38
NetR103_2: R103.2 U3.6 | length 104.4
  Top Signal w10: R103.2@548.62,4835 U3.6@652.99,4835
NetR104_2: R104.2 U3.7 | length 104.4
  Top Signal w10: R104.2@548.62,4785 U3.7@652.99,4785
QEP1_SEL: S5.5 U14.9 U14.10 U14.11 | length 750
  Top Signal w5: S5.5@997.34,1550.5 v1(1044.5,1550.5) ; v1(1434.5,1550.5) 1434.5,1291.28 U14.9@1436.21,1289.57 U14.10@1436.21,1263.98 U14.11@1436.21,1238.39
  Bottom Signal w5: v1(1044.5,1550.5) v1(1434.5,1550.5)
QEP2_SEL: S5.2 U11.9 U11.10 U11.11 | length 378.5
  Top Signal w5: U11.11@1035.83,1238.39 U11.10@1035.83,1263.98 U11.9@1035.83,1289.57 1035.83,1322.59 1086.02,1372.78 1086.02,1531.02 1105.5,1550.5 S5.2@1143.01,1550.5
SCI_SEL1: S2.2 U6.1 U6.5 U9.1 U9.5 | length 1006.1
  Top Signal w5: U6.1@912.38,3976.76 944.24,3976.76 950,3971 950,3905 943.02,3898.02 U6.5@912.38,3898.02 914.05,3896.35 v1(914.05,3830) ; S2.2@1210.98,3527.63 1222.63,3527.63 1261.53,3566.53 1261.53,3750 ; v1(1261.53,3830) U9.1@1261.53,3787.4 1261.53,3750 ; U9.5@1340.27,3787.4 1340.27,3755 1335.27,3750 1261.53,3750
  Bottom Signal w5: v1(914.05,3830) v1(1261.53,3830)
SCI_SEL2: S2.5 U8.1 U8.5 | length 2418.4
  Top Signal w5: U8.5@437.4,2016.13 478.08,2016.13 485,2023.05 485,2088.37 478.5,2094.87 450,2094.87 v1(450,3025) ; v1(1215,3025) 1215,3335 1300.75,3420.75 1300.75,3484.12 1307.99,3491.36 ; 1307.99,3491.61 1344.01,3527.63 S2.5@1356.65,3527.63
  Bottom Signal w5: v1(450,3025) v1(1215,3025) v1@1216.38,3025
USB_DM: R103.1 U100.5 USB101.2 | length 593.7
  Top Signal w8: USB101.2@419.41,5290 USB101.2@419.41,5298.19 ; USB101.2@420,5290 420,5250 395,5225 v1(395,5210) 395,5205 405,5195 U100.5@423.19,5195 ; v1(440,4840) R103.1@495,4840
  Bottom Signal w8: v1(395,5210) 405,5210 450,5165 450,4850 v1(440,4840)
USB_DP: R104.1 U100.4 USB101.3 | length 629.2
  Top Signal w8: U100.4@423.19,5214.69 423.19,5223.19 445,5245 USB101.3@445,5298.19 ; v1(450,4780) R104.1@496.38,4780 R104.1@500,4780
  Top Signal w12: USB101.3@443.81,5297 USB101.3@445,5298.19
  Bottom Signal w8: v1(443.81,5250) 443.81,5216.19 465,5195 465,4795 v1(450,4780)
USB_GND: C100.2 C101.2 C103.2 C104.2 C105.1 C106.1 JP1.1 L100.2 LED0.1 R100.1 R102.1 U3.2 U3.8 U100.3 U101.6 U101.9@170,5000 | length 1068.5
  Top Signal w8: v1(365,4770) LED0.1@365,4813.66 ; U100.3@446.81,5214.69 464.69,5214.69 475,5225 v1@475,5230 ; v1@474,5230 v1@474,5231
  Top Signal w10: v1(560,4630) v1(740,4630) ; v1@591.38,5035 v1(591.5,5035) ; C104.2@650,4630.73 v1(650,4685)
  Top Signal w12: R102.1@143.62,4880 144.62,4879 v1(187,4879) ; U101.6@157.2,4944.88 157.2,4917.8 165,4910 v1(175,4910)
  Top Signal w20: C103.2@80,4996.38 U101.9@166.38,4996.38 ; v1(585,4735) 652.99,4735 653.99,4734 v1(717,4734)
  Top Signal w25: v1(415,5035) v1@591.38,5035 ; v1(585,5175) 591.5,5181.5 L100.2@591.5,5220 ; v1(591.5,5035) 652.99,5035 v1(716,5035) ; v1(660,5200) R100.1@660,5246.38 ; v1(710,5200) C101.2@710,5246.38
  other v1: 170,4977.36 132.6,5000 207.4,5000 170,5022.64 478,5226
USB_ID: U100.2 USB101.4 | length 156
  Top Signal w8: U100.2@446.81,5195 480,5195 498,5213 498,5238.87 471.87,5265 471.87,5293.13 USB101.4@470.59,5294.41 ; USB101.4@470,5295 USB101.4@470.59,5294.41 ; USB101.4@470.59,5298.19 USB101.4@470.59,5294.41
USB_VBUS: C100.1 C105.2 JP3.1 L101.2 U3.1 U100.6 U101.1 U101.2 U101.8 | length 460.1
  Top Signal w5: v1(395,5175) 400,5175 400.31,5175.31 U100.6@423.19,5175.31 ; v1(591.23,5083.62) v1@591.5,5083.62
  Top Signal w10: L101.2@260,5178.5 L101.2@261.5,5180
  Top Signal w12: U101.2@182.8,5055.12 195,5067.32 195,5068.5 ; v1(195,5090) 195,5068.5 ; v1(208.39,4921.61) U101.8@208.39,4944.88 ; U101.1@208.39,5055.12 195,5068.5
  Top Signal w20: v1(260,5130) L101.2@260,5178.5 ; v1(420,5080) 422.76,5080 426.38,5083.62 C100.1@460,5083.62
  Top Signal w25: C100.1@460,5083.62 C105.2@560,5083.62 v1(591.23,5083.62) ; v1@591.5,5083.62 651.61,5083.62 652.99,5085 v1(717,5085)
USB_VCC: C102.1 C103.1 JP2.1 R101.2 R105.2 U101.3 U101.4
VDD: C9.2 C10.1 C11.1 C12.1 C13.1 TP1.1 U1.8 U1.31 U1.53 U1.71 | length 507.2
  Top Signal w10: v1(958.3,2831.83) U1.8@997.56,2792.56 ; U1.31@969.73,2376.37 v1(1005,2411.65) 1043.35,2411.65 v1(1085,2370) ; U1.71@1330.24,2764.73 1359.25,2793.74 v1(1359.25,2815) ; U1.53@1372,2418.13 v1(1415,2375.13)
  Bottom Signal w10: C9.2@932.27,2862.27 932.27,2857.86 v1(958.3,2831.83) 981.58,2831.83 C13.1@991.7,2821.7 ; C12.1@994.37,2383.3 1005,2393.93 v1(1005,2411.65) ; C10.1@1333.3,2796.7 1340.96,2796.7 v1(1359.25,2815) ; C11.1@1388.3,2398.3 1391.83,2398.3 v1(1415,2375.13)
VDDA: C14.2 C15.1 L2.1 TP3.1 U1.26 | length 210.9
  Top Signal w10: U1.26@900.13,2445.97 v1(932.27,2478.11)
  Bottom Signal w10: v1(932.27,2478.11) 962.67,2508.51
  Bottom Signal w12: v1(655,2560) 655,2570 L2.1@690,2605 ; C14.2@939.3,2531 941.03,2531 C15.1@984.3,2487.73
VDDIO: C19.1 C20.2 C21.2 C22.2 C23.2 L3.2 TP2.1 U1.7 U1.32 U1.52 U1.72 | length 484.7
  Top Signal w10: v1(965,2304.59) 965,2343.81 U1.32@983.64,2362.45 ; U1.7@1011.48,2806.48 v1(1050,2767.97) ; v1(1277.67,2740) U1.72@1316.32,2778.64 ; v1(1317.29,2445) U1.52@1358.08,2404.21
  Bottom Signal w10: L3.2@933.46,2260 965,2291.54 v1(965,2304.59) 965,2342.67 C21.2@959.37,2348.3 ; C20.2@1026.7,2786.7 1031.26,2786.7 v1(1050,2767.97) 1061.58,2767.97 C19.1@1087.27,2742.27 ; v1(1277.67,2740) 1298.3,2760.62 C23.2@1298.3,2761.7 ; v1(1317.29,2445) 1340.14,2445 C22.2@1351.85,2433.3
XDS_DM: R1.2 U2.93 | length 874.9
  Top Signal w6: R1.2@1163.62,4840 1188.62,4815 v1(1205,4815) ; v1(1613,4935) 1754.85,5076.85 U2.93@1903.15,5076.85
  Bottom Signal w6: v1(1205,4815) 1225,4795 1473,4795 v1(1613,4935)
XDS_DP: R2.2 U2.94 | length 869
  Top Signal w6: R2.2@1163.62,4780 1205,4780 v1(1240,4815) ; v1(1613.62,4965.24) 1740.98,5092.6 U2.94@1903.15,5092.6
  Bottom Signal w6: v1(1240,4815) 1463.39,4815 v1(1613.62,4965.24)
XDS_RESET_OUT: J102.10 R57.1 U2.40 U12.2 | length 452.2
  Top Signal w5: U12.2@1451.57,4450 v1(1480,4450) 1480,4422 1470,4412 R57.1@1470,4274.93 1485.58,4274.93 1525,4235.51 J102.10@1525,4194.88 ; v1(1466.14,4530) U2.40@1466.14,4576.85
  Bottom Signal w5: v1(1466.14,4530) 1480,4516.14 v1(1480,4450)
XDS_RXD: J101.3 U2.33 | length 295.7
  Top Signal w5: J101.3@1250,4325 1250,4435.11 1355.91,4541.01 U2.33@1355.91,4576.85
XDS_TCK_SWDCLK: J101.7 J102.4 U2.35 U12.6 | length 1154.4
  Top Signal w5: U2.35@1387.4,4576.85 1387.4,4542.4 1365.51,4520.51 1365.51,4477.4 1370,4472.91 v1(1370,4450) ; U12.6@1398.43,4450 v1(1370,4450) ; J102.4@1675,4194.88 1675,4156.42 1645,4126.42 1477.58,4126.42 1440,4164 1440,4328.43 1370,4398.43 v1(1370,4450)
  Bottom Signal w5: J101.7@1050,4325 1175,4450 v1(1370,4450)
XDS_TDI: J102.8 U2.38 U12.3 | length 490
  Top Signal w5: U2.38@1434.65,4576.85 1434.65,4534.35 1460.09,4508.91 1460.09,4485.54 1460,4485.45 1460,4478.11 U12.3@1451.57,4469.68 1486.81,4469.68 1500,4456.5 1500,4300 1515,4285 1552.83,4285 1575,4262.83 J102.8@1575,4194.88
XDS_TDO_SWO: J102.6 U2.37 U12.5 | length 511.1
  Top Signal w5: U12.5@1398.43,4469.68 1398.43,4484.67 1412.6,4498.85 v1(1412.6,4502.4) 1412.6,4546.51 1418.9,4552.8 U2.37@1418.9,4576.85 ; J102.6@1625,4194.88 v1(1625,4265)
  Bottom Signal w5: v1(1412.6,4502.4) 1412.6,4477.4 v1(1625,4265)
XDS_TMS_SWDIO: J101.5 J102.2 U2.36 U12.7 | length 1000.4
  Top Signal w5: v1(1385,4510) 1402.6,4527.6 1402.6,4574.7 1403.15,4575.24 U2.36@1403.15,4576.85 ; U12.7@1398.43,4430.31 1400,4428.74 v1(1400,4408.05) ; J102.2@1725,4194.88 1725,4215 v1(1760,4215)
  Bottom Signal w5: J101.5@1150,4325 1233.05,4408.05 v1(1400,4408.05) ; v1(1385,4510) 1385,4489.7 1400,4474.7 v1(1400,4408.05) ; v1(1760,4215) 1566.59,4215 1400,4381.59 v1(1400,4408.05)
XDS_TXD: J101.1 U2.34 | length 260.8
  Top Signal w5: J101.1@1350,4325 1350,4519.14 1371.65,4540.8 U2.34@1371.65,4576.85
XRSn: C7.1 C17.2 J4/J2.16 J8/J6.56 R4.1 R5.2 R11.1 S1.4 U1.5 | length 5093.6
  Top Signal w5: v1(995,3000) 995,2878.64 U1.5@1039.32,2834.32 ; J8/J6.56@2050,1125 2140,1215 2140,2240 2185,2285 v1(2185,3000) 2185,3490 J4/J2.16@2050,3625 2097.64,3672.64 2097.64,4167.36 2090,4175 2090,4325.98 2121.69,4357.68 S1.4@2152.44,4357.68 2152.44,4561.92 R4.1@2149.61,4564.76 R5.2@2199.61,4564.76 C7.1@2249.61,4564.76
  Bottom Signal w5: v1(995,3000) v1(2185,3000)
XTAL_X1: C42.1 R33.2 Y2.3 | length 181.2
  Top Signal w6: v1(1520,2110) 1536.41,2110 1559.72,2133.31 Y2.3@1567.83,2133.31 1586.5,2151.97 R33.2@1586.5,2200
  Bottom Signal w6: v1(1520,2110) 1564.21,2110 C42.1@1567.83,2113.62
XTAL_X2: C41.1 R32.2 Y2.1 | length 285.8
  Top Signal w6: v1(1385,2083.86) 1385,2075 1413.31,2046.69 Y2.1@1422.17,2046.69 1431.69,2046.69 1469.43,2084.43 1469.43,2187.42 R32.2@1456.85,2200
  Bottom Signal w6: v1(1385,2083.86) 1404.69,2083.86 C41.1@1422.17,2066.38
pads on no net: FID1.1 FID2.1 FID3.1 FID4.1 FID5.1 FID6.1 J1/J3.6 J5/J7.46 J8/J6.57 J8/J6.71 J8/J6.72 J8/J6.73 J10.7 J10.MH1 J10.MH2 J10.MH3 J11.9 J102.7 M1.0 M2.0 M3.0 M4.0 M5.0 M6.0 M7.0 M8.0 M9.0 MH1.1 MH2.1 MH3.1 MH4.1 S1. U1.33 U1.34 U2.1 U2.2 U2.5 U2.6 U2.11 U2.12 U2.13 U2.14 U2.15 U2.18 U2.19 U2.20 U2.21 U2.22 U2.23 U2.24 U2.25 U2.27 U2.29 U2.30 U2.31 U2.32 U2.41 U2.42 U2.43 U2.44 U2.45 U2.46 U2.49 U2.50 U2.53 U2.54 U2.56 U2.57 U2.65 U2.67 U2.71 U2.72 U2.73 U2.74 U2.75 U2.76 U2.77 U2.78 U2.81 U2.82 U2.83 U2.84 U2.85 U2.86 U2.91 U2.92 U2.95 U2.102 U2.103 U2.104 U2.105 U2.106 U2.107 U2.108 U2.109 U2.110 U2.111 U2.112 U2.116 U2.117 U2.118 U2.119 U2.120 U2.121 U2.123 U2.124 U2.125 U2.126 U2.127 U2.128 U12.1 U101.7 U101.9@145.2,5000 U101.9@194.8,5000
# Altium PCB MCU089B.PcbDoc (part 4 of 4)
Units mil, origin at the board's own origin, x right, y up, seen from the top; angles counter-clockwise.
Board outline 2300 x 5500 mil, 4 copper layers (Top Signal, GND, PWR, Bottom Signal), stack 61.6 mil thick; 261 components, 208 nets, 964 pads, 377 vias.

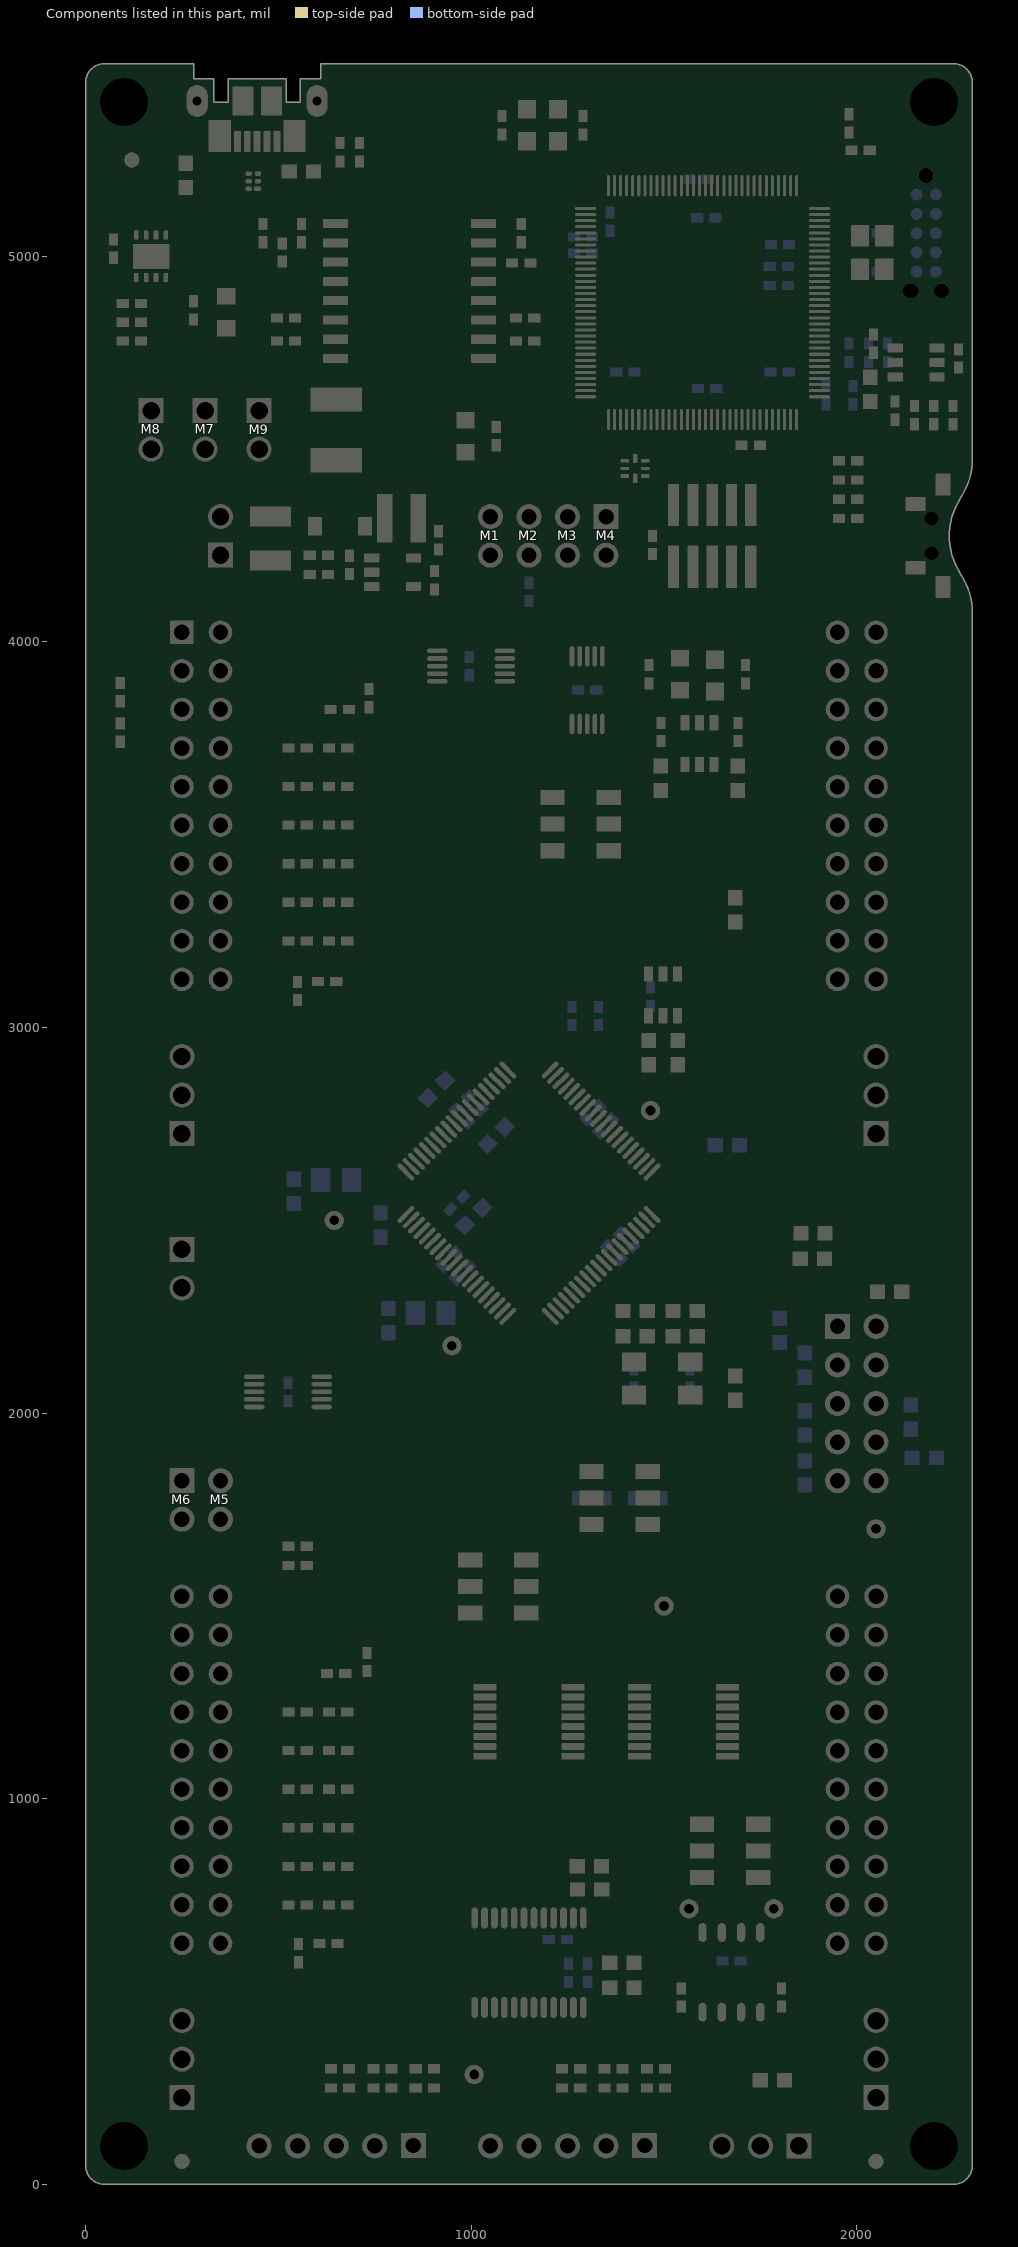
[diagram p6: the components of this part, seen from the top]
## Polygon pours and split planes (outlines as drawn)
+3V3 on Top Signal "TOP_SIGNAL_+3V3_P044" (solid, remove dead copper, pour order 44): 885,4160 860,4185 835,4185 815,4205 815,4230.49 830,4245.49 830,4380 850,4400 885,4400 905,4380 905,4300 930,4275 930,4160
NetD1_2 on Top Signal "TOP_SIGNAL_NETD1_2_P042" (solid, remove dead copper, pour order 42): 685,4355 730,4400 805,4400 810,4395 815,4390 815,4250 795,4230 795,4210 795,4200 785,4200 725,4200 710,4215 710,4240.31 685,4265.24
NetC3_2 on Top Signal "TOP_SIGNAL_NETC3_2_P040" (solid, remove dead copper, pour order 40): 604.8,4241.86 685,4241.77 685,4195 715,4165 775,4165 775,4125 760,4110 650,4110 604.8,4155.2
NetC3_1 on Top Signal "TOP_SIGNAL_NETC3_1_P038" (solid, remove dead copper, pour order 38): 350,4274.93 304.99,4275.01 285,4295 285,4360 305,4380 610,4380 640,4350 640,4260 615,4260 591.5,4236.5 591.5,4155 546.95,4155 540,4161.95 540,4249.93 515,4274.93
NetC106_2 on Top Signal "TOP_SIGNAL_NETC106_2_P030" (solid, remove dead copper, pour order 30): 730,5010 730,4855 485,4855 460,4880 460,5010
USB_VCC on Top Signal "TOP_SIGNAL_USB_VCC_P028" (solid, remove dead copper, pour order 28): 220,4570 250,4600 250,4735 325,4810 325,5065 240,5150 110,5150 50,5090 50,4630 110,4570
+5V0 on Bottom Signal "BOTTOM_SIGNAL_+5V0_P020" (solid, remove dead copper, pour order 20): 865,5500 865,4645 745,4525 0,4525 0,0 1520,0 1520,525 1496,545 500,545 400,645 400,4370 430,4400 800,4400 1000,4600 1000,5300 1050,5350 2000,5350 2050,5400 2050,5500
+3V3 on PWR "PWR_+3V3_P054" (solid, remove dead copper, pour order 54): 865,5500 2300,5500 2300,0 0,0 0,4525 745,4525 865,4645
NetC59_1 on PWR "PWR_NETC59_1_P052" (solid, remove dead copper, pour order 52): 1840,5013.7 1665,5188.7 1645,5208.7 1560,5208.7 1550,5208.7 1510,5168.7 1510,5118.7 1720,4908.7 1880,4908.7 1910,4938.7 1910,4993.7 1890,5013.7
VDDA on PWR "PWR_VDDA_P050" (solid, remove dead copper, pour order 50): 850,2350 945,2350 1080,2485 1080,2694.86 994.86,2780 940,2780 823.19,2663.19 707.98,2662.98 635,2590 635,2470 730,2470
VDD on PWR "PWR_VDD_P048" (solid, remove dead copper, pour order 48): 1065,2370 1095,2400 1300.29,2400 1327.44,2400 1420,2492.56 1420,2650 1265,2805 1025,2805 1010,2790 960,2790 938.25,2811.75 938.25,2856.51 1006.75,2925 1324,2925 1550,2699 1550,2450 1420,2320 1090,2320 1065,2345
VDDIO on PWR "PWR_VDDIO_P046" (solid, remove dead copper, pour order 46): 909.05,2165 909.05,2299.05 1090,2480 1090,2700 1022.29,2767.71 1022.29,2787.29 1030,2795 1255,2795 1410,2640 1410,2500 1320,2410 1100,2410 990,2300 990,2165
USB_VBUS on PWR "PWR_USB_VBUS_P032" (solid, remove dead copper, pour order 32): 0,5500 815,5500 815,4665 725,4575 0,4575
GND on GND "GND_GND_P036" (solid, remove dead copper, pour order 36): 865,5500 2300,5500 2300,0 0,0 0,4525 745,4525 865,4645
USB_GND on GND "GND_USB_GND_P034" (solid, remove dead copper, pour order 34): 0,4575 725,4575 815,4665 815,5500 0,5500

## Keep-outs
Keep-Out Layer:
  text ".Layer_Name" at 577,-858.49 h60

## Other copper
Top Signal:
  text ".Layer_Name" at 577,-858.49 h60
Bottom Signal:
  text ".Layer_Name" at 577,-858.49 h60

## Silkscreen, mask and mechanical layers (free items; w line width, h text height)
Top Overlay:
  drawing of 11724 lines, arcs and shapes, not listed
  text "XDS110 Out" at 1485,4440 h30
  text "+3V3" at 110,4405 h30
  text "+5V0" at 250,4405 h30
  text "GND" at 410,4405 h30
  text "XRSn" at 1980,4230 h72.83
  text "+5V0 / Boost" at 128.88,4180 h30
  text "TCK" at 1033,4156 h30 r270
  text "TMS" at 1133,4156 h30 r270
  text "TXD<<" at 1233,4156 h30 r270
  text "RXD>>" at 1333,4156 h30 r270
  text "IO.0" at 1785.5,4010.25 h30
  text "C6" at 133,3909.75 h30
  text "IO.1" at 1795,3910 h30
  text "IO.5" at 2114.5,3910.43 h30
  text "IO." at 130,3830 h30
  text "IO.40" at 2114.5,3815 h30
  text "A6" at 413.5,3810 h30
  text "IO.2" at 1785,3810 h30
  text "28" at 126.5,3790 h30
  text "A3" at 413.5,3730 h25
  text "*" at 2253.5,3715 h25
  text "IO.3" at 1785.5,3710 h30
  text "IO.18" at 2114.5,3710 h30
  text "C5" at 413.5,3695 h25
  text "IO.29" at 53,3660 h30
  text "1" at 1170.75,3635 h30
  text "1" at 1388.62,3635 h30
  text "A2" at 413,3630 h25
  text "IO.4" at 1785.5,3610 h30
  text "XRSn" at 2114.5,3610 h30
  text "C9" at 413,3595 h25
  text "SEL1" at 1136.2,3575 h30 r270
  text "SEL2" at 1402.35,3575 h30 r270
  text "A15" at 413,3530 h25
  text "NC" at 133,3510 h30
  text "IO.15" at 1760,3510 h30
  text "IO.11" at 2114.5,3510 h30
  text "C7" at 413,3495 h25
  text "A14" at 413,3431.33 h25
  text "IO.9" at 83,3410 h30
  text "IO.42" at 1755,3410 h30
  text "IO.10" at 2114.5,3410 h30
  text "C4" at 413.5,3395.75 h25
  text "0" at 1165.75,3395 h30
  text "0" at 1388.62,3395 h30
  text "A11" at 413,3330 h25
  text "SEL1:" at 813.35,3322.5 h35
  text "IO28," at 990.66,3322.5 h35
  text "IO16," at 1171.04,3322.5 h35
  text "*" at 1732,3315 h25
  text "IO.34" at 53.5,3310 h30
  text "IO.19" at 1760,3310 h30
  text "IO.23" at 2114.5,3310 h30
  text "C0" at 413,3295 h25
  text "SEL2" at 813.35,3272.5 h35
  text "IO29" at 990.66,3272.5 h35
  text "IO17" at 1171.04,3272.5 h35
  text "A12" at 413,3230 h25
  text "*" at 1727,3215 h25
  text ":" at 881.66,3212 h35
  text "IO.43" at 53.5,3210 h30
  text "IO.39" at 1755,3210 h30
  text "IO.8" at 2114.5,3210 h30
  text "0" at 846.66,3208 h35
  text "0" at 900.28,3208 h35
  text "XDS" at 1015.04,3208 h35
  text "BP" at 1208.33,3208 h35
  text "C1" at 413,3195 h25
  text ":" at 882.53,3149.5 h35
  text "0" at 847.53,3145.5 h35
  text "1" at 907.53,3145.5 h35
  text "XDS" at 1015.04,3145.5 h35
  text "NC" at 1208.33,3145.5 h35
  text "IO.22" at 410,3125 h25
  text "IO.26" at 53,3110 h30
  text "IO.25" at 1755,3110 h30
  text "IO.27" at 2114.5,3110 h30
  text "DAC" at 413,3090 h25
  text ":" at 882.75,3087.5 h35
  text "1" at 852.75,3083.5 h35
  text "0" at 901.37,3083.5 h35
  text "BP" at 1037.04,3083.5 h35
  text "BP" at 1208.33,3083.5 h35
  text ":" at 883.1,3026.08 h35
  text "1" at 853.1,3022.08 h35
  text "1" at 908.1,3022.08 h35
  text "BP" at 1037.04,3022.08 h35
  text "XDS" at 1191.79,3022.08 h35
  text "VDD" at 1505,2753.3 h30
  text "VDDA" at 495,2465 h30
  text "*" at 1675,2455 h25
  text "VREFHI" at 19.5,2408 h30
  text "*" at 1343,2310 h25
  text "*" at 1620,2310 h25
  text "FSI" at 1916.38,2280 h30
  text "TXCLK" at 2110,2200 h30
  text "RXCLK" at 1720,2195 h30
  text "VDDIO" at 775,2140 h30
  text "TXD0" at 2110,2000 h30
  text "RXD0" at 1755,1990 h30
  text "1" at 1484.96,1900 h30
  text "RXD1" at 1775,1895 h30
  text "TXD1" at 2110,1895 h30
  text "LAUNCHXL- / F280025C" at 685,1877.95 h50
  text "GPIO24" at 1235,1862 h30 r270
  text "GPIO32" at 1505,1862.5 h30 r270
  text "+5V0 / TO / J7" at 420,1705 h30
  text "+3V3 / TO / J5" at 60,1700 h30
  text "GND" at 1935,1670 h30
  text "BOOT" at 1330,1625 h30
  text "0" at 1480,1625 h30
  text "BP" at 900,1605 h30
  text "BP" at 1190,1605 h30
  text "Q1" at 910,1535.05 h30
  text "Q2" at 1190,1535.05 h30
  text "IO.12" at 1758,1510 h30
  text "J12" at 875,1465 h30
  text "J13" at 1190,1465 h30
  text "+3V3" at 1535,1465 h30
  text "A1" at 143,1410 h30
  text "IO.13" at 1758,1410 h30
  text "IO.33" at 2114.5,1410 h30
  text "QEP Select" at 915,1390 h35
  text "A5" at 413.27,1330 h25
  text "IO.35" at 53,1310 h30
  text "IO.14" at 2114.62,1310 h30
  text "IO.6" at 1783,1305 h30
  text "C2" at 413.27,1295 h25
  text "A7" at 413,1230 h25
  text "NC" at 2114.62,1210 h30
  text "IO.7" at 1783,1200 h30
  text "C3" at 413,1195 h25
  text "IO.24" at 53,1160 h30
  text "A8" at 413,1130 h25
  text "IO.16" at 1758,1110 h30
  text "XRSn" at 2114.62,1110 h30
  text "C11" at 413,1095 h25
  text "A4" at 413,1035 h25
  text "NC" at 133,1010 h30
  text "IO.17" at 1760,1010 h30
  text "IO.30" at 2114.5,1010 h30
  text "C14" at 413,1000 h25
  text "CAN / ROUTE" at 1596.73,990 h30
  text "A9" at 413,936.33 h25
  text "IO." at 1830,933.9 h30
  text "BP" at 1501.73,920 h30
  text "IO.22" at 53,910 h30
  text "IO.31" at 2114.5,910 h30
  text "C8" at 413.5,900.75 h25
  text "45" at 1830,885 h30
  text "A10" at 413,835 h25
  text "IO.41" at 63,810 h30
  text "IO.39" at 2114.5,810 h30
  text "NC" at 1834.5,805 h30
  text "C10" at 413,800 h25
  text "XCVR" at 1440,780 h30
  text "A0" at 413,735 h25
  text "IO.37" at 53,710 h30
  text "NC" at 1834.5,710 h30
  text "IO.32" at 2114.5,710 h30
  text "C15" at 413,700 h25
  text "IO.23" at 410,630 h25
  text "IO.44" at 53,610 h30
  text "NC" at 1834.5,610 h30
  text "IO.46" at 2114.5,610 h30
  text "DAC" at 413,595 h25
  text "+5V0" at 1042.73,270 h30
  text "EQEP2" at 580,170 h30
  text "EQEP1" at 1185,170 h30
  text "CAN" at 1760,170 h30
  text "GND" at 410,10 h30
  text "5V" at 525,10 h30
  text "2I" at 628.62,10 h30
  text "2B" at 725,10 h30
  text "2A" at 825,10 h30
  text "GND" at 1010,10 h30
  text "5V" at 1125,10 h30
  text "1I" at 1234.25,10 h30
  text "1B" at 1330,10 h30
  text "1A" at 1430,10 h30
  text "GND" at 1610,10 h30
  text "LO" at 1725,10 h30
  text "HI" at 1830,10 h30
  text ".Layer_Name" at 577,-858.49 h60
Bottom Overlay:
  drawing of 12858 lines, arcs and shapes, not listed
  text "LAUNCHXL-F280025C / Development Kit" at 2300,5270 h100
  text "www.ti.com/launchpad" at 2300,4375 h100
  text "40" at 1883,4010 h30
  text "39" at 1883,3915 h30
  text "2" at 183,3910 h30
  text "19" at 2162,3910 h30
  text "38" at 1883,3815 h30
  text "3" at 183,3810 h30
  text "23" at 467,3810 h30
  text "18" at 2162,3810 h30
  text "4" at 183,3710 h30
  text "24" at 467,3710 h30
  text "37" at 1883,3710 h30
  text "17" at 2162,3710 h30
  text "5" at 183,3610 h30
  text "25" at 467,3610 h30
  text "36" at 1883,3610 h30
  text "16" at 2162,3610 h30
  text "6" at 183,3510 h30
  text "26" at 467,3510 h30
  text "35" at 1883,3510 h30
  text "15" at 2162,3510 h30
  text "'.PRJ_Number'.PCB_Rev" at 1409.9,3445 h108.27
  text "7" at 183,3410 h30
  text "27" at 467,3410 h30
  text "34" at 1883,3410 h30
  text "14" at 2162,3410 h30
  text "8" at 183,3310 h30
  text "28" at 467,3310 h30
  text "33" at 1883,3310 h30
  text "13" at 2162,3310 h30
  text "9" at 183,3210 h30
  text "29" at 467,3210 h30
  text "32" at 1883,3210 h30
  text "12" at 2162,3210 h30
  text "10" at 183,3110 h30
  text "30" at 467,3110 h30
  text "31" at 1883,3110 h30
  text "11" at 2152,3110 h30
  text "80" at 1883,1515 h30
  text "42" at 183,1410 h30
  text "79" at 1883,1410 h30
  text "59" at 2167,1409.55 h30
  text "43" at 183,1310 h30
  text "63" at 467,1310 h30
  text "78" at 1883,1310 h30
  text "58" at 2167,1309.55 h30
  text "44" at 183,1210 h30
  text "64" at 467,1210 h30
  text "77" at 1883,1210 h30
  text "57" at 2167,1209.55 h30
  text "45" at 183,1110 h30
  text "65" at 467,1110 h30
  text "76" at 1883,1110 h30
  text "56" at 2167,1109.55 h30
  text "46" at 183,1010 h30
  text "66" at 467,1010 h30
  text "75" at 1883,1010 h30
  text "55" at 2167,1009.55 h30
  text "47" at 183,910 h30
  text "67" at 467,910 h30
  text "74" at 1883,910 h30
  text "54" at 2167,909.55 h30
  text "48" at 183,810 h30
  text "68" at 467,810 h30
  text "73" at 1883,810 h30
  text "53" at 2167,809.55 h30
  text "49" at 183,710 h30
  text "69" at 467,710 h30
  text "72" at 1883,710 h30
  text "52" at 2167,709.55 h30
  text "50" at 183,610 h30
  text "70" at 467,610 h30
  text "71" at 1883,610 h30
  text "51" at 2157,610 h30
  text "GND" at 490,15 h30
  text "5V" at 575,15 h30
  text "2I" at 675,15 h30
  text "2B" at 775,15 h30
  text "2A" at 875,15 h30
  text "GND" at 1090,15 h30
  text "5V" at 1175,15 h30
  text "1I" at 1266.64,15 h30
  text "1B" at 1370,15 h30
  text "1A" at 1470,15 h30
  text ".Layer_Name" at 577,-858.49 h60
Top Paste:
  text ".Layer_Name" at 577,-858.49 h60
Bottom Paste:
  text ".Layer_Name" at 577,-858.49 h60
Top Solder:
  text ".Layer_Name" at 577,-858.49 h60
  text ".Layer_Name" at 577,-858.49 h60
Bottom Solder:
  text ".Layer_Name" at 577,-858.49 h60
Drill Guide:
  text ".Layer_Name" at 577,-858.49 h60
M1 Board Outline:
  the board outline again, w10
  text ".Layer_Name" at 577,-858.49 h60
M2 Board Dimensions:
  rectangle: 125,-400 500,-275
  rectangle: 0,-275 125,-150
  lines w7: 0,-275 1000,-275 ; 125,-400 125,-150 ; 250,-400 250,-150 ; 500,-400 500,-150 ; 750,-400 750,-150 ; 0,-400 0,-150 1000,-150 1000,-400 0,-400
  text "Radius 50 mil, 4 corners" at 2406,-202 h100
  text ".Layer_Name" at 577,-858.49 h60
M3 3D STEP Top:
  text ".Layer_Name" at 577,-858.49 h60
M4 3D STEP Bottom:
  text ".Layer_Name" at 577,-858.49 h60
M5 Assembly Top:
  lines w10: -292,-930.17 6308,-930.17 ; -292,-726.83 6310,-726.83 ; -292,-523.5 -292,-1133.5 3713,-1133.5 6310,-1133.5 6310,-523.5 -291.5,-523.5 -291.5,-1133.5 1284,-1133.5 ; 2173,-1133.5 2173,-523.5 ; 3440,-726.83 3440,-523.5 ; 4280,-726.83 4280,-523.5 ; 4902,-1140 4902,-937.17
  text "Place all Shunts (9 total) as described  in Figure 1 of Test Procedure." at 75,6810 h40
  text "Ensure that all switches are placed in the proper direction with default positions as described in Figure 1 of Test Procedure" at 75,6710 h40
  text "COMPONENTS MARKED 'DNP' SHOULD NOT BE POPULATED." at 1153.5,-318.5 h60
  text "ASSEMBLY VARIANT:" at 1153,-434 h60
  text ".VariantName" at 2189,-434 h60
  text "PCB VIEWED FROM TOP SIDE" at -228.5,-655.67 h60
  text "BOARD #:" at 2248,-655.67 h60
  text ".PRJ_Number" at 2793.5,-655.67 h60
  text "REV:" at 3638,-655.67 h60
  text ".PCB_Rev" at 3929.5,-655.67 h60
  text "SVN REV:" at 4476,-655.67 h60
  text ".VersionControl_RevNumber" at 4982,-655.67 h60
  text "TID #:" at 2248,-859 h60
  text ".TID" at 2793.5,-859 h60
  text ".Layer_Name" at 580,-860 h60
  text "PLOT NAME =" at -228.5,-1064.34 h60
  text ".plot_File_Name" at 577,-1064.34 h60
  text "GENERATED    :" at 2250,-1064.34 h60
  text ".Print_Date" at 3119.5,-1064.34 h60
  text ".Print_Time" at 3848.5,-1064.34 h60
  text "TEXAS INSTRUMENTS" at 5113,-1064.34 h60
M6 Assembly Bottom:
  lines w10: -292.5,-727.33 6309.5,-727.33 ; -290.5,-930.67 6309.5,-930.67 ; 1115.5,-1140.5 1115.5,-937.67 ; 1737.5,-727.33 1737.5,-524 ; 2577.5,-727.33 2577.5,-524 ; 3844.5,-1134 3844.5,-524 ; 4733.5,-1134 6309,-1134 6309,-524 -292.5,-524 -292.5,-1134 2304.5,-1134 6309.5,-1134 6309.5,-524
  text "COMPONENTS MARKED 'DNP' SHOULD NOT BE POPULATED." at 6102,-318 h60
  text ".VariantName" at 5058,-434 h60
  text "ASSEMBLY VARIANT:" at 6097,-434 h60
  text ".VersionControl_RevNumber" at 1035.5,-656.17 h60
  text "SVN REV:" at 1541.5,-656.17 h60
  text ".PCB_Rev" at 2088,-656.17 h60
  text "REV:" at 2379.5,-656.17 h60
  text ".PRJ_Number" at 3224,-656.17 h60
  text "BOARD #:" at 3769.5,-656.17 h60
  text "PCB VIEWED FROM BOTTOM SIDE" at 6246,-656.17 h60
  text ".Layer_Name" at 580,-860 h60
  text ".TID" at 3224,-859.5 h60
  text "TID #:" at 3769.5,-859.5 h60
  text "TEXAS INSTRUMENTS" at 904.5,-1064.84 h60
  text ".Print_Time" at 2169,-1064.84 h60
  text ".Print_Date" at 2898,-1064.84 h60
  text "GENERATED    :" at 3767.5,-1064.84 h60
  text ".plot_File_Name" at 5440.5,-1064.84 h60
  text "PLOT NAME =" at 6246,-1064.84 h60
M7 LPKF Text Top:
  text ".Layer_Name" at 580,-860 h60
M8 LPKF Text Bottom:
  text ".Layer_Name" at 580,-860 h60
M9 Title Sheet:
  drawing of 57 lines, arcs and shapes, not listed
  text "1" at 739.84,8036.5 h70
  text "2" at 3235.5,8036.5 h70
  text "3" at 5724.84,8036.5 h70
  text "4" at 8231.51,8036.5 h70
  text "5" at 10730.5,8036.5 h70
  text "6" at 13235.5,8036.5 h70
  text "A" at -416.5,6893.5 h70
  text "A" at 14383.5,6893.5 h70
  text "B" at -416.5,4513.5 h70
  text "B" at 14383.5,4513.5 h70
  text "C" at -416.5,2138.5 h70
  text "C" at 14383.5,2138.5 h70
  text "PROJECT TITLE:" at 11343.5,277.5 h45
  text ".PRJ_Title" at 11393.5,144.17 h70
  text "DESIGNED FOR:" at 11343.5,-23.5 h45
  text ".PRJ_Customer" at 11393.5,-163.5 h70
  text "D" at -416.5,-231.5 h70
  text "D" at 14383.5,-231.5 h70
  text "FILE NAME:" at 11343.5,-323.5 h45
  text ".PCB_File_Name_No_Path" at 11393.5,-443.5 h70
  text "Texas Instruments (TI) and/or its licensors do not warrant the accuracy or completeness of this specification" at 6374,-605.34 h45
  text "ENGINEER:" at 11343.5,-613.5 h45
  text "LAYOUT BY:" at 12848.5,-613.5 h45
  text "or any information contained therein. TI and/or its licensors do not warrant that this design will meet" at 6329.01,-718 h45
  text ".PRJ_Engineer" at 11393.5,-768.49 h70
  text ".PCB_Layout" at 12899,-768.49 h70
  text "the specifications, will be suitable for your application or fit for any particular purpose, or will operate in" at 6329.01,-830.67 h45
  text ".Layer_Name" at 577,-858.49 h60
  text "ALTIUM DESIGNER VERSION:" at 12848.5,-923.5 h45
  text "an implementation. TI and/or its licensors do not warrant that the design is production worthy. You should" at 6329.01,-943.33 h45
  text "completely validate and test your design implementation to confirm the system functionality for your application." at 6374,-1056 h45
  text ".print_Scale" at 11393.5,-1056.83 h70
  text ".Application_BuildNumber" at 12899,-1056.83 h70
  text "1" at 739.84,-1263.5 h70
  text "2" at 3235.5,-1263.5 h70
  text "3" at 5724.84,-1263.5 h70
  text "4" at 8231.51,-1263.5 h70
  text "5" at 10730.5,-1263.5 h70
  text "6" at 13235.5,-1263.5 h70
M10 Fab Notes:
  drawing of 189 lines, arcs and shapes, not listed
  text "DESIGN INFORMATION" at 12382.02,6356.17 h60
  text "MIN. TRACK WIDTH:" at 11737.46,6224.05 h60
  text "5" at 12833.7,6224.05 h60
  text "MIL" at 12988.46,6224.05 h60
  text "MIN. CLEARANCE:" at 11737.46,6099.92 h60
  text "0.2" at 12773.7,6099.93 h60
  text "mm" at 12988.46,6099.92 h60
  text "MIN. VIA PAD SIZE:" at 11737.46,5975.8 h60
  text "22" at 12803.71,5975.8 h60
  text "MIL" at 12988.46,5975.8 h60
  text "0.05mm (2MIL)" at 12432.46,5845.9 h60
  text "MINIMUM ANNULAR RING" at 11408.23,5837.67 h60
  text "EXTERNAL" at 13140.46,5837.67 h60
  text "PER" at 11608.23,5727.55 h60
  text "IPC-D-275 CLASS 2 LEVEL C" at 11828.23,5727.54 h60
  text "MIL, HOLES" at 13316.46,5627.07 h60
  text "+/-" at 12924,5618.48 h60
  text "+/-" at 13778,5618.48 h60
  text "REGISTRATION TOLERANCES:" at 11408.23,5617.42 h60
  text "METAL" at 12608,5617.42 h60
  text "5" at 13184.2,5617.42 h60
  text "3" at 14017.2,5617.42 h60
  text "MIL" at 14133.46,5617.42 h60
  text "HOLE SIZE TOLERANCE (UNLESS OTHERWISE SPECIFIED):" at 11408.23,5519.1 h60
  text "+/-" at 13778,5516.23 h60
  text "5" at 14017.2,5515.17 h60
  text "MIL" at 14133.46,5515.17 h60
  text "MATERIAL:" at 11333.46,5377.52 h60
  text "FR-4 High Tg" at 12319.9,5249 h60
  text "X" at 12175.46,5241.01 h60
  text "FR-408" at 11754.46,5236.49 h60
  text "OTHER" at 13242.46,5236.49 h60
  text "62 MIL (1.6mm) +/-10%" at 12074.56,5093.46 h60
  text "X" at 11954.46,5091.01 h60
  text "THICKNESS:" at 11408.23,5085.24 h60
  text "OTHER" at 13359.46,5085.24 h60
  text "TOLERANCE:" at 11408.23,4946.92 h60
  text "ANSI IPC-6012 TYPE 3 CLASS 2" at 12434.48,4946.92 h60
  text "IPC-A600" at 13120,4820 h72.83
  text "OTHER +/-" at 12434.46,4802.73 h60
  text "X" at 12265,4800 h60
  text "BOW & TWIST:" at 11408.23,4657.54 h60
  text "ANSI IPC-6012 TYPE 3 CLASS 2" at 12434.48,4657.54 h60
  text "X" at 12255,4535 h60
  text "IPC-A600" at 13120,4515 h72.83
  text "OTHER +/-" at 12434.46,4510.85 h60
  text "DRILLING:" at 11333.46,4380.23 h60
  text "NC_DRILL FILES" at 13094.46,4275.04 h60
  text "REFERENCE:" at 11408.23,4271.1 h60
  text "X" at 12065.46,4271.01 h60
  text "AS SHOWN" at 12243.46,4271.1 h60
  text "X" at 12966.46,4271.1 h60
  text "OTHER" at 13392.46,4128.85 h60
  text "PTH COPPER THICKNESS:" at 11407.91,4125.32 h60
  text "X" at 12547.14,4125.32 h60
  text "20-30 um" at 12675.14,4125.32 h60
  text "BOARD FINISH:" at 11333.46,3977.73 h60
  text "SILKSCREEN:" at 11488.68,3867.6 h60
  text "X" at 12446.46,3867.6 h60
  text "TOP" at 12563.46,3867.6 h60
  text "X" at 12956.46,3867.6 h60
  text "BOTTOM" at 13074.46,3867.6 h60
  text "SILKSCREEN COLOR:" at 11488.68,3712.41 h60
  text "X" at 12445.46,3712.41 h60
  text "WHITE" at 12563.46,3712.41 h60
  text "OTHER" at 13074.46,3712.41 h60
  text "RED" at 13712,3579 h80
  text "GREEN" at 12694.46,3568.96 h60
  text "OTHER" at 13312.46,3568.96 h60
  text "X" at 13166,3565 h60
  text "SOLDER RESIST COLOR:" at 11488.68,3562.1 h60
  text "MATTE" at 12694.46,3414.71 h60
  text "SEMI-GLOSS" at 13312,3414.07 h60
  text "IMMERSION GOLD (ENIG)" at 12394.46,3241.94 h60
  text "ENEPIG" at 13732,3234.72 h60
  text "SURFACE FINISH:" at 11333.46,3233.72 h60
  text "IMM. TIN/SILVER OR EQUIV" at 11663,3096.4 h60
  text "X" at 11515,3095 h60
  text "OTHER" at 13094.46,3092.47 h60
  text "ARRAY/PANEL:" at 11333.46,2937.09 h60
  text "CUT AND TRIM PER M1 BOARD OUTLINE" at 12394.46,2928.87 h60
  text "X" at 12216,2927 h60
  text "N.C. ROUTE" at 12394.46,2792.9 h60
  text "V. SCORE" at 13260.46,2792.9 h60
  text "CERTIFICATION:" at 11333.46,2663.77 h60
  text "MATERIALS AND WORKMANSHIP FOR ALL PCBS" at 12058.46,2663.77 h60
  text "TO MEET OR EXCEED THE REQUIREMENTS OF:" at 12058.46,2569.71 h60
  text "X" at 13472.97,2443.39 h60
  text "X" at 11695.97,2441.08 h60
  text "ANSI IPC-A-600F CLASS ->" at 11823.96,2441.08 h60
  text "2" at 13581.96,2441.08 h60
  text "1" at 13266.96,2439.58 h60
  text "3" at 13935.96,2439.58 h60
  text "X" at 12507.97,2293.39 h60
  text "RoHS" at 12635.96,2293.39 h60
  text "OTHER" at 13280.36,2293.39 h60
  text "PER ORDER" at 13677.42,2293.39 h60
  text "ALL BOARDS MUST MEET OR EXCEED UL94-V0 REQUIREMENTS." at 11361,2139.57 h60
  text "PCB MUST BEAR THE UL94V-0 UL REGISTERED MATERIAL ID NUMBER" at 11361,2023.5 h60
  text "ADDITIONAL REQUIREMENTS:" at 11333.46,1854.08 h60
  text "MICROSECTION:" at 11408.23,1746.95 h60
  text "YES" at 12313.96,1746.95 h60
  text "X" at 12592,1605 h60
  text "REQUIRED" at 13175.46,1602.62 h60
  text "BARE BOARD ELEC. TEST:" at 11408.23,1599.76 h60
  text "NONE" at 12713.96,1599.76 h60
  text "PER ORDER" at 13767.46,1599.76 h60
  text "XX MIL VIAS REQUIRE NON-CONDUCTIVE FILL AND PLANARIZE" at 11576.38,1394.82 h59
  text "XX MIL VIAS REQUIRE CONDUCTIVE FILL AND PLANARIZE" at 11584.38,1290.84 h60
  text "OUTER XX MIL VIAS REQUIRE 50 OHM SINGLE-ENDED IMPEDANCE" at 11583.39,1127.46 h58
  text "LAYER 2 & 3 (INNER LAYERS) XX MIL WIDE, XX MIL SPACE / TRACES REQUIRE 100 OHM DIFFERENTIAL IMPEDANCE" at 11575.39,891.74 h60
  text ".Layer_Name" at 577,-858.49 h60
M11 Gerber Information:
  lines w10: -292,-930.17 6308,-930.17 ; -292,-726.83 6310,-726.83 ; -292,-523.5 -292,-1133.5 3713,-1133.5 6310,-1133.5 6310,-523.5 -291.5,-523.5 -291.5,-1133.5 1284,-1133.5 ; 2173,-1133.5 2173,-523.5 ; 3440,-726.83 3440,-523.5 ; 4280,-726.83 4280,-523.5 ; 4902,-1140 4902,-937.17
  text "ALL ARTWORK VIEWED FROM TOP SIDE" at -228.5,-655.67 h60
  text "BOARD #:" at 2248,-655.67 h60
  text ".PRJ_Number" at 2793.5,-655.67 h60
  text "REV:" at 3638,-655.67 h60
  text ".PCB_Rev" at 3929.5,-655.67 h60
  text "SVN REV:" at 4476,-655.67 h60
  text ".VersionControl_RevNumber" at 4982,-655.67 h60
  text "LAYER NAME =" at -228.5,-858.49 h60
  text "TID #:" at 2248,-859 h60
  text ".TID" at 2793.5,-859 h60
  text ".Layer_Name" at 580,-860 h60
  text "PLOT NAME =" at -228.5,-1064.34 h60
  text ".plot_File_Name" at 577,-1064.34 h60
  text "GENERATED    :" at 2250,-1064.34 h60
  text ".Print_Date" at 3119.5,-1064.34 h60
  text ".Print_Time" at 3848.5,-1064.34 h60
  text "TEXAS INSTRUMENTS" at 5113,-1064.34 h60
M12 Stackup:
  drawing of 295 lines, arcs and shapes, not listed
  text "Layer" at 6515.58,6390 h60
  text "Name" at 6925.49,6390 h60
  text "Material" at 7855.23,6390 h60
  text "Thickness" at 8715,6390 h60
  text "Constant" at 9364.84,6390 h60
  text "Board Layer Stack" at 9934.7,6390 h60
  text "Top Overlay" at 6925.49,6270 h60
  text "Top Solder" at 6925.49,6150 h60
  text "Solder Resist" at 7855.23,6150 h60
  text "0.40mil" at 8715,6150 h60
  text "3.5" at 9364.84,6150 h60
  text "1" at 6515.58,6030 h60
  text "Top Signal" at 6925.49,6030 h60
  text "Copper" at 7855.23,6030 h60
  text "1.40mil" at 8715,6030 h60
  text "Dielectric 1" at 6925.49,5910 h60
  text "FR-4" at 7855.23,5910 h60
  text "8.00mil" at 8715,5910 h60
  text "4.2" at 9364.84,5910 h60
  text "2" at 6515.58,5790 h60
  text "GND" at 6925.49,5790 h60
  text "Copper" at 7855.23,5790 h60
  text "1.40mil" at 8715,5790 h60
  text "Dielectric 2" at 6925.49,5670 h60
  text "FR-4" at 7855.23,5670 h60
  text "40.00mil" at 8715,5670 h60
  text "4.2" at 9364.84,5670 h60
  text "3" at 6515.58,5550 h60
  text "PWR" at 6925.49,5550 h60
  text "Copper" at 7855.23,5550 h60
  text "1.40mil" at 8715,5550 h60
  text "Dielectric 3" at 6925.49,5430 h60
  text "FR-4" at 7855.23,5430 h60
  text "8.00mil" at 8715,5430 h60
  text "4.2" at 9364.84,5430 h60
  text "4" at 6515.58,5310 h60
  text "Bottom Signal" at 6925.49,5310 h60
  text "Copper" at 7855.23,5310 h60
  text "1.40mil" at 8715,5310 h60
  text "Bottom Solder" at 6925.49,5190 h60
  text "Solder Resist" at 7855.23,5190 h60
  text "0.40mil" at 8715,5190 h60
  text "3.5" at 9364.84,5190 h60
  text "Bottom Overlay" at 6925.49,5070 h60
  text "Use Standard 4 Layer Stackup" at 7340,4835 h250
  text ".Layer_Name" at 577,-858.49 h60
M13 Component Bodies Top:
  text ".Layer_Name" at 577,-858.49 h60
M14 Component Bodies Bottom:
  text ".Layer_Name" at 577,-858.49 h60
M15 Courtyards Top:
  text ".Layer_Name" at 577,-858.49 h60
M16 Courtyards Bottom:
  text ".Layer_Name" at 577,-858.49 h60
Drill Drawing:
  circle w10: c5363.63,3723.98 r16.56
  circle w10: c5363.63,3723.98 r27.59
  circle w10: c5363.63,3227.28 r27.59
  lines w10: 5336.04,2633.99 5391.23,2633.99 5363.63,2578.8 5336.04,2633.99 ; 5336.04,2716.78 5349.83,2716.78 5363.63,2702.98 5377.43,2716.78 5391.23,2716.78 5377.43,2730.57 5391.23,2744.37 5377.43,2744.37 5363.63,2758.17 5349.83,2744.37 5336.04,2744.37 5349.83,2730.57 5336.04,2716.78 ; 5336.04,2854.75 5363.63,2827.16 5391.23,2854.75 5363.63,2882.35 5336.04,2854.75 ; 5336.04,2965.13 5349.83,2965.13 5349.83,2951.33 5377.43,2951.33 5377.43,2965.13 5391.23,2965.13 5391.23,2992.72 5377.43,2992.72 5377.43,3006.52 5349.83,3006.52 5349.83,2992.72 5336.04,2992.72 5336.04,2965.13 ; 5336.04,3075.51 5363.63,3089.31 5391.23,3075.51 5377.43,3103.1 5391.23,3130.7 5363.63,3116.9 5336.04,3130.7 5349.83,3103.1 5336.04,3075.51 ; 5336.04,3323.86 5391.23,3323.86 5391.23,3379.05 5336.04,3379.05 5336.04,3323.86 ; 5336.04,3448.04 5336.04,3461.83 5349.83,3475.63 5336.04,3489.43 5336.04,3503.23 5349.83,3503.23 5363.63,3489.43 5377.43,3503.23 5391.23,3503.23 5391.23,3489.43 5377.43,3475.63 5391.23,3461.83 5391.23,3448.04 5377.43,3448.04 5363.63,3461.83 5349.83,3448.04 5336.04,3448.04 ; 5336.04,3572.21 5391.23,3572.21 5391.23,3627.4 5336.04,3627.4 5336.04,3572.21 ; 5347.07,3086.55 5363.63,3094.82 5380.19,3086.55 5371.91,3103.1 5380.19,3119.66 5363.63,3111.38 5347.07,3119.66 5355.35,3103.1 5347.07,3086.55 ; 5347.07,3334.9 5380.19,3334.9 5380.19,3368.01 5347.07,3368.01 5347.07,3334.9
  lines w12: 5286,2541.55 8547.72,2541.55 ; 5286,3783.31 8547.72,3783.31 ; 5623.86,2417.38 5623.86,3907.49 ; 5955.86,2417.38 5955.86,3907.49 ; 6592.42,2417.38 6592.42,3907.49 ; 6851.53,2417.38 6851.53,3907.49 ; 7226.68,2417.38 7226.68,3907.49 ; 7981.26,2417.38 7981.26,3907.49 ; 5286,2417.38 8547.72,2417.38 8547.72,3907.49 5286,3907.49 5286,2417.38
  text "Symbol" at 5360.51,3820.56 h72
  text "Quantity" at 5661.11,3820.56 h72
  text "Finished Hole Size" at 5993.12,3820.56 h72
  text "Plated" at 6629.67,3820.56 h72
  text "Hole Type" at 6888.78,3820.56 h72
  text "Drill Layer Pair" at 7263.93,3820.56 h72
  text "Hole Tolerance" at 8018.52,3820.56 h72
  text "2" at 5661.11,3696.39 h60
  text "35.43mil (0.900mm)" at 5993.12,3696.39 h60
  text "NPTH" at 6629.67,3696.39 h60
  text "Round" at 6888.78,3696.39 h60
  text "Top Signal - Bottom Signal" at 7263.93,3696.39 h60
  text "3" at 5661.11,3572.21 h60
  text "39.00mil (0.991mm)" at 5993.12,3572.21 h60
  text "NPTH" at 6629.67,3572.21 h60
  text "Round" at 6888.78,3572.21 h60
  text "Top Signal - Bottom Signal" at 7263.93,3572.21 h60
  text "4" at 5661.11,3448.04 h60
  text "125.00mil (3.175mm)" at 5993.12,3448.04 h60
  text "NPTH" at 6629.67,3448.04 h60
  text "Round" at 6888.78,3448.04 h60
  text "Top Signal - Bottom Signal" at 7263.93,3448.04 h60
  text "274" at 5661.11,3323.86 h60
  text "10.00mil (0.254mm)" at 5993.12,3323.86 h60
  text "PTH" at 6629.67,3323.86 h60
  text "Round" at 6888.78,3323.86 h60
  text "Top Signal - Bottom Signal" at 7263.93,3323.86 h60
  text "103" at 5661.11,3199.68 h60
  text "10.00mil (0.254mm)" at 5993.12,3199.68 h60
  text "PTH" at 6629.67,3199.68 h60
  text "Round" at 6888.78,3199.68 h60
  text "Top Signal - Bottom Signal" at 7263.93,3199.68 h60
  text "+/-5.00mil" at 8018.52,3199.68 h60
  text "8" at 5661.11,3075.51 h60
  text "25.00mil (0.635mm)" at 5993.12,3075.51 h60
  text "PTH" at 6629.67,3075.51 h60
  text "Round" at 6888.78,3075.51 h60
  text "Top Signal - Bottom Signal" at 7263.93,3075.51 h60
  text "32" at 5661.11,2951.33 h60
  text "40.00mil (1.016mm)" at 5993.12,2951.33 h60
  text "PTH" at 6629.67,2951.33 h60
  text "Round" at 6888.78,2951.33 h60
  text "Top Signal - Bottom Signal" at 7263.93,2951.33 h60
  text "80" at 5661.11,2827.16 h60
  text "40.16mil (1.020mm)" at 5993.12,2827.16 h60
  text "PTH" at 6629.67,2827.16 h60
  text "Round" at 6888.78,2827.16 h60
  text "Top Signal - Bottom Signal" at 7263.93,2827.16 h60
  text "25" at 5661.11,2702.98 h60
  text "45.28mil (1.150mm)" at 5993.12,2702.98 h60
  text "PTH" at 6629.67,2702.98 h60
  text "Round" at 6888.78,2702.98 h60
  text "Top Signal - Bottom Signal" at 7263.93,2702.98 h60
  text "2" at 5661.11,2578.8 h60
  text "23.62mil (0.600mm)" at 5993.12,2578.8 h60
  text "PTH" at 6629.67,2578.8 h60
  text "Slot" at 6888.78,2578.8 h60
  text "Top Signal - Bottom Signal" at 7263.93,2578.8 h60
  text "533 Total" at 5661.11,2454.63 h60
  text "Slot definitions :" at 5360.51,2367.71 h60
  text "Routed Path Length" at 5810.51,2367.71 h60
  text "= Calculated from tool start centre position to tool end centre position." at 6349.42,2367.71 h60
  text "Hole Length" at 5810.51,2318.03 h60
  text "= Routed Path Length + Tool Size = Slot length as defined in the PCB layout" at 6149.91,2318.03 h60
  text ".Layer_Name" at 577,-858.49 h60
Mechanical 17:
  text ".Layer_Name" at 577,-858.49 h60
Mechanical 18:
  text ".Layer_Name" at 577,-858.49 h60
Mechanical 19:
  text ".Layer_Name" at 577,-858.49 h60

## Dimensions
2118.33,4075 to 2438,4077 on M2 Board Dimensions
2118.33,4475 to 2461,4460 on M2 Board Dimensions
2421.67,4275 to 2400,4275 on M2 Board Dimensions
2250,50 to 2375,-65 on M2 Board Dimensions
0,0 to 2300,0 on M2 Board Dimensions
0,0 to 0,5500 on M2 Board Dimensions
0,-400 to 1000,-400 on M2 Board Dimensions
